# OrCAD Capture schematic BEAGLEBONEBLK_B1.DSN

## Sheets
1 P01_Title Page: title: BeagleBone Black Cover Page; rev: B; note: 450-5500-001
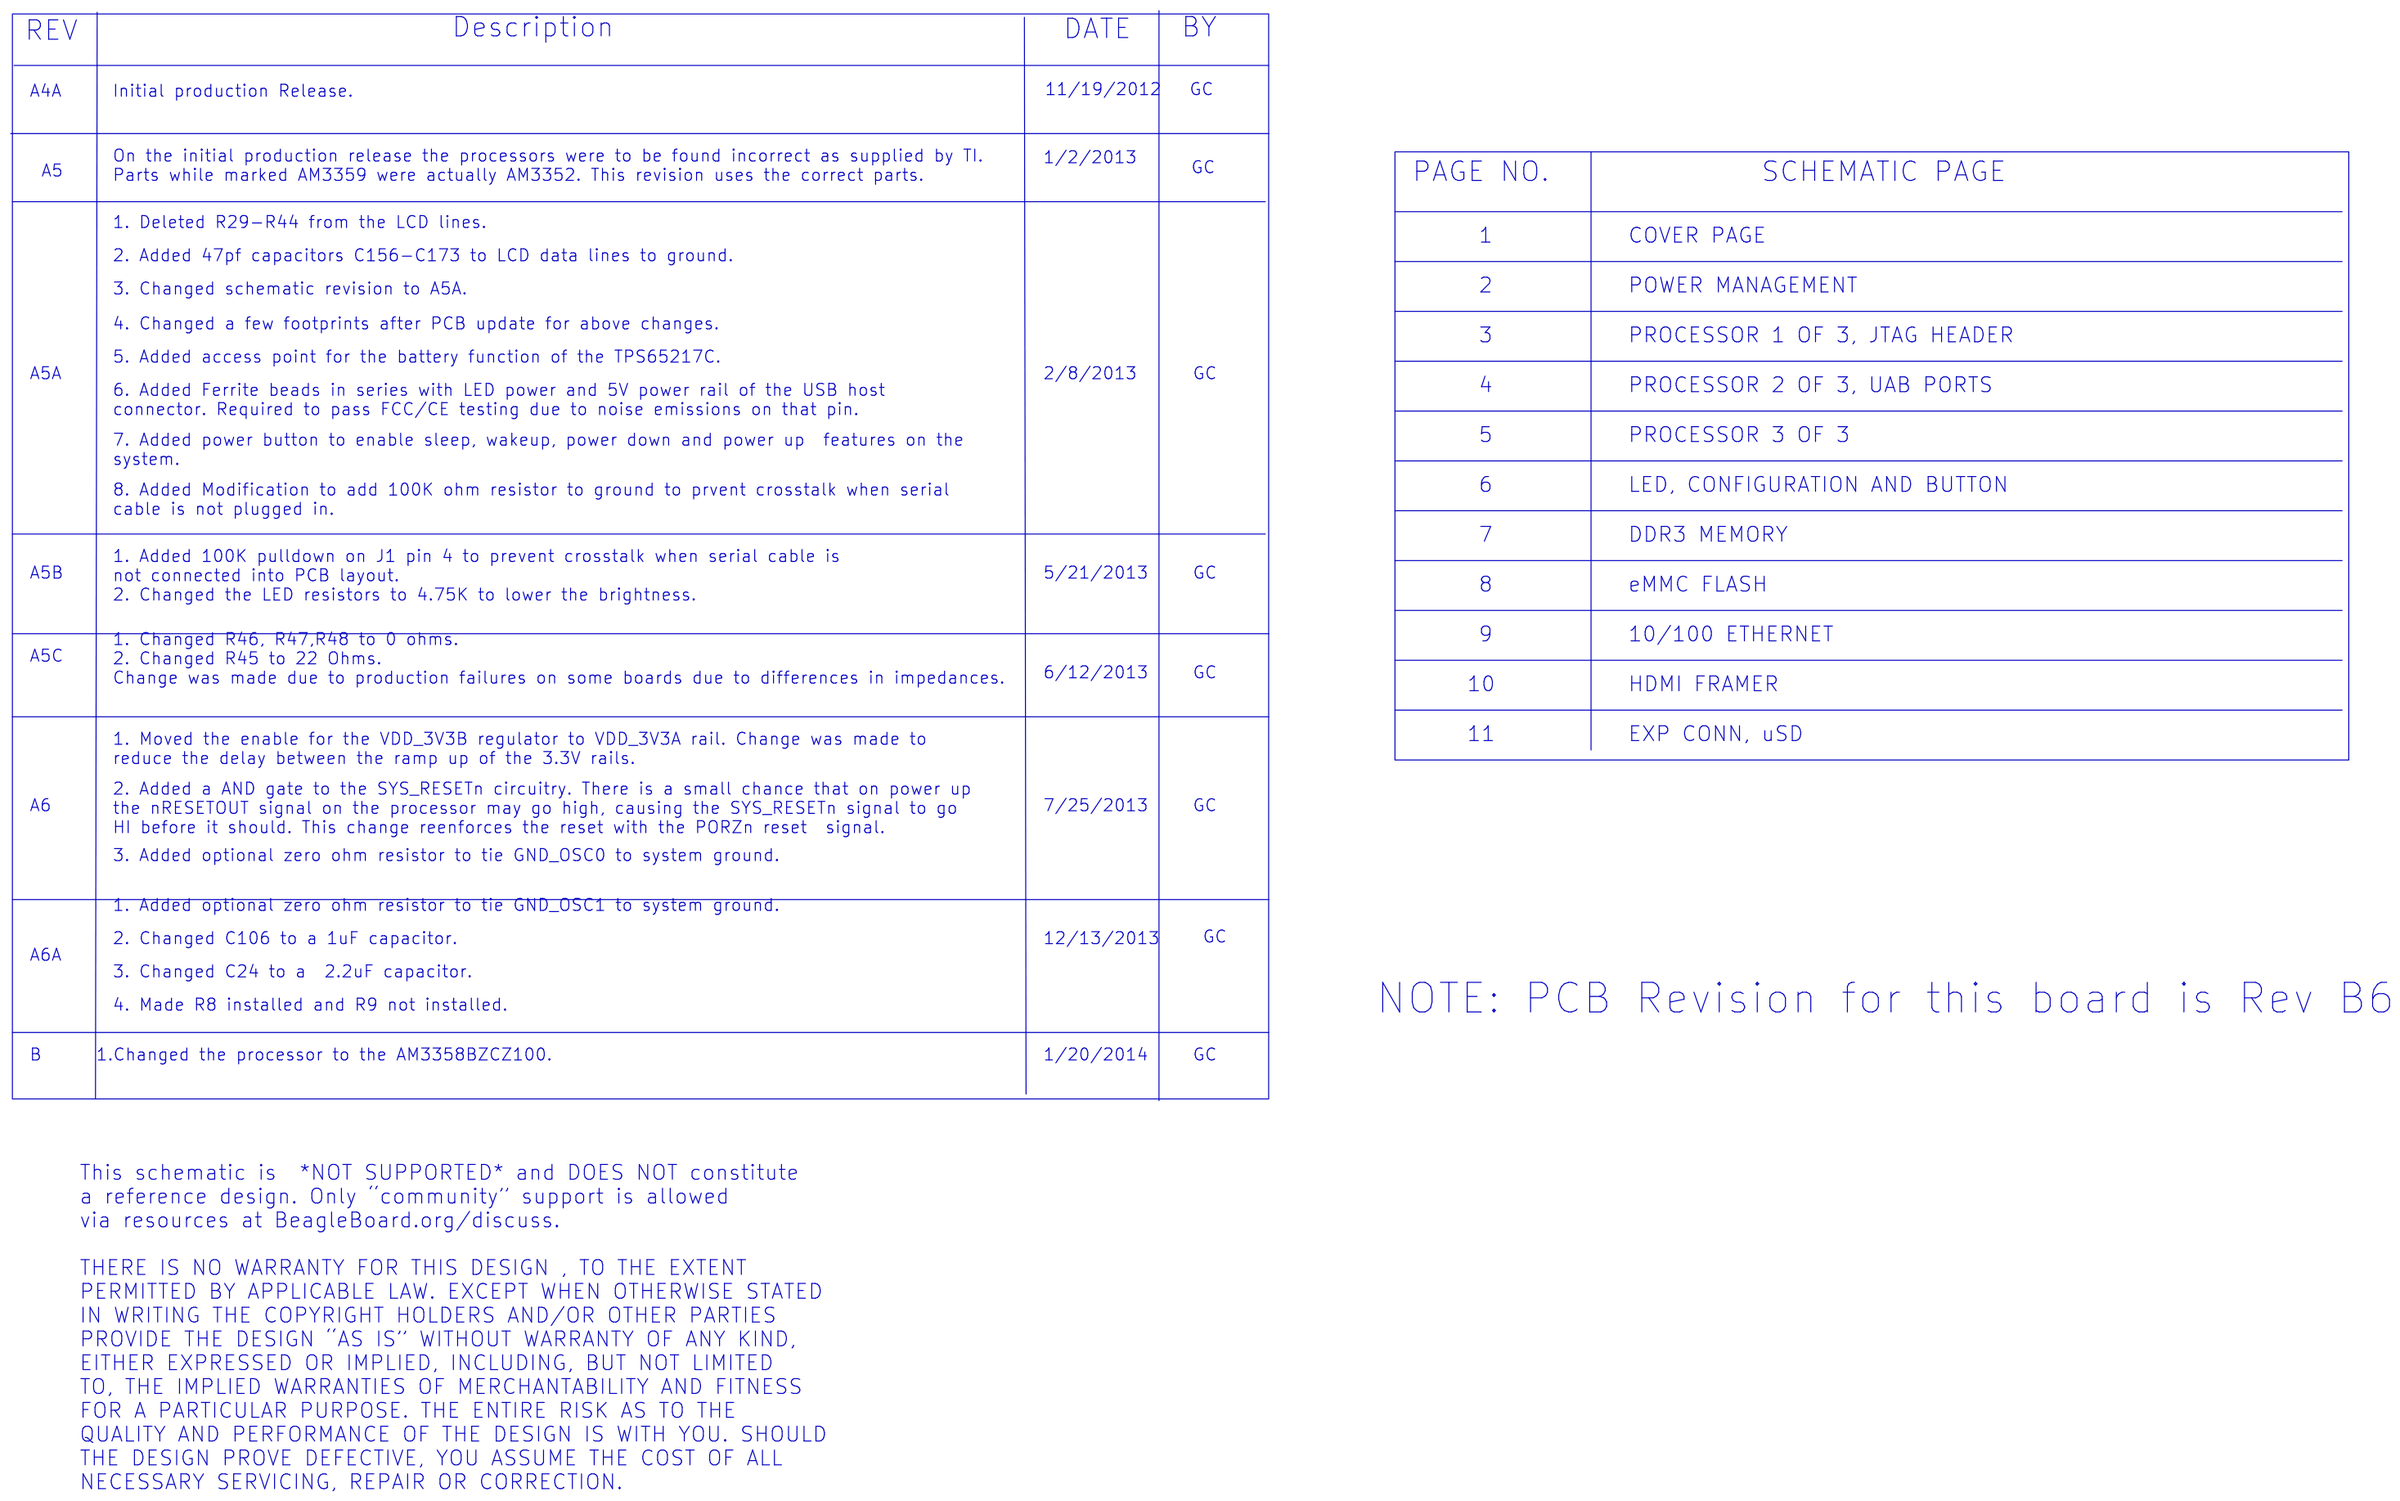
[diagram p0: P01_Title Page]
2 P02_Power Management: size B; title: BeagleBone Black Power Management
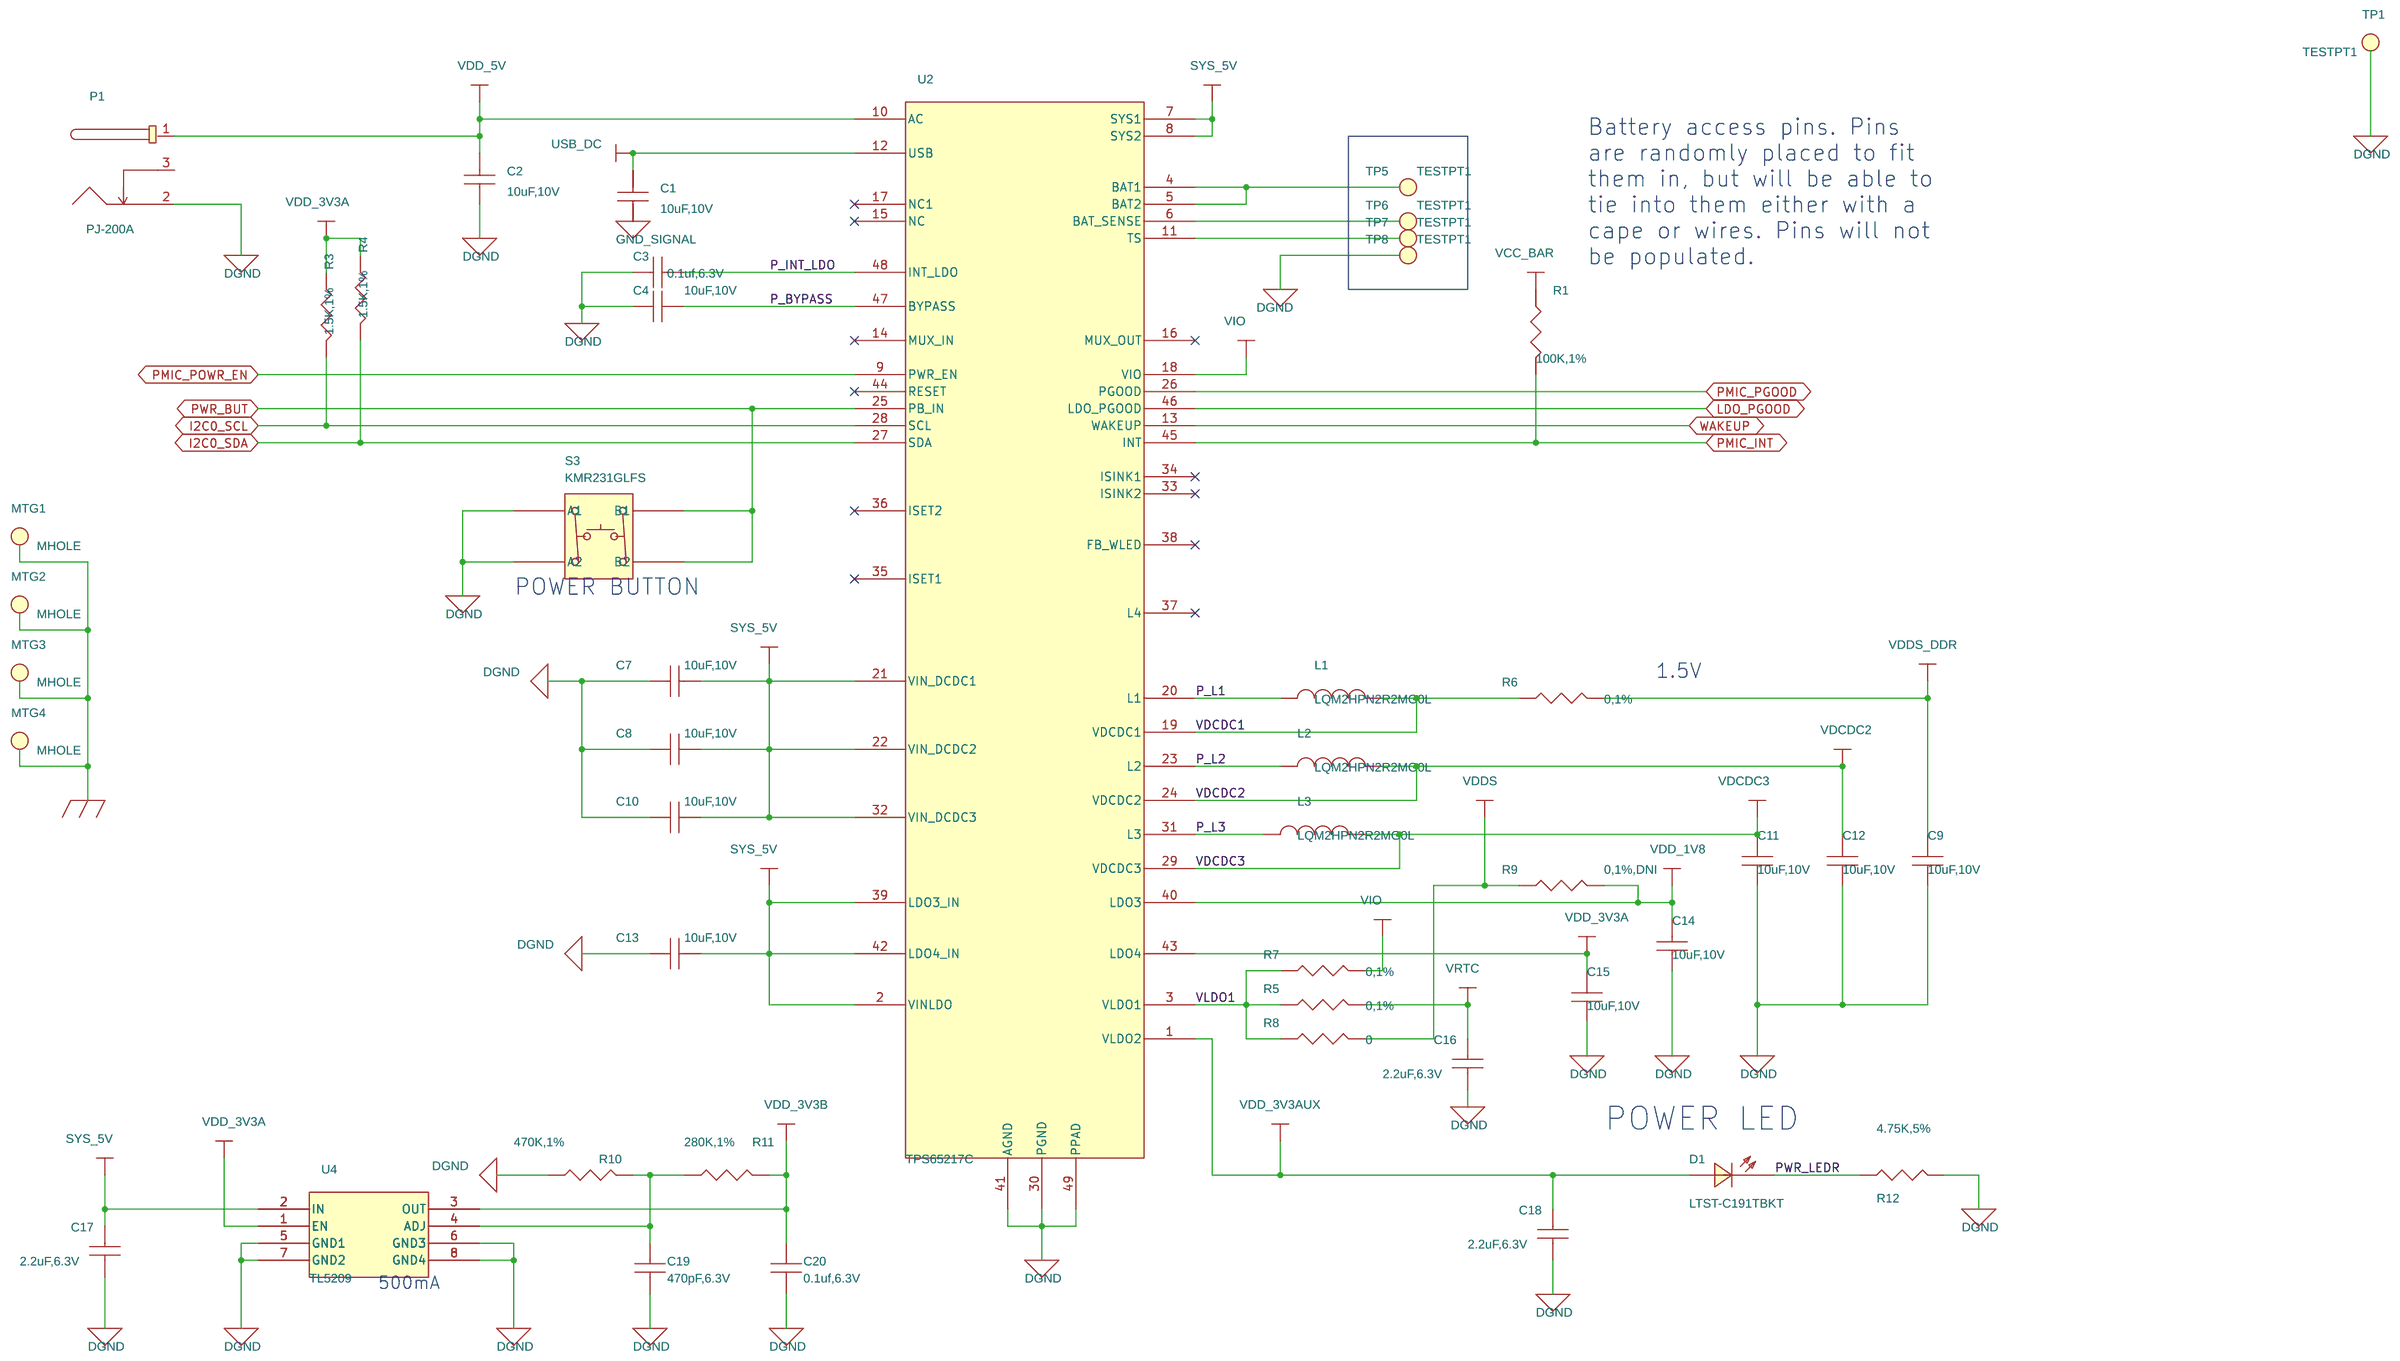
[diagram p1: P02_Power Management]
3 P06_LED, Config: size B; title: BeagleBone Black LED, Configuration, and Reset
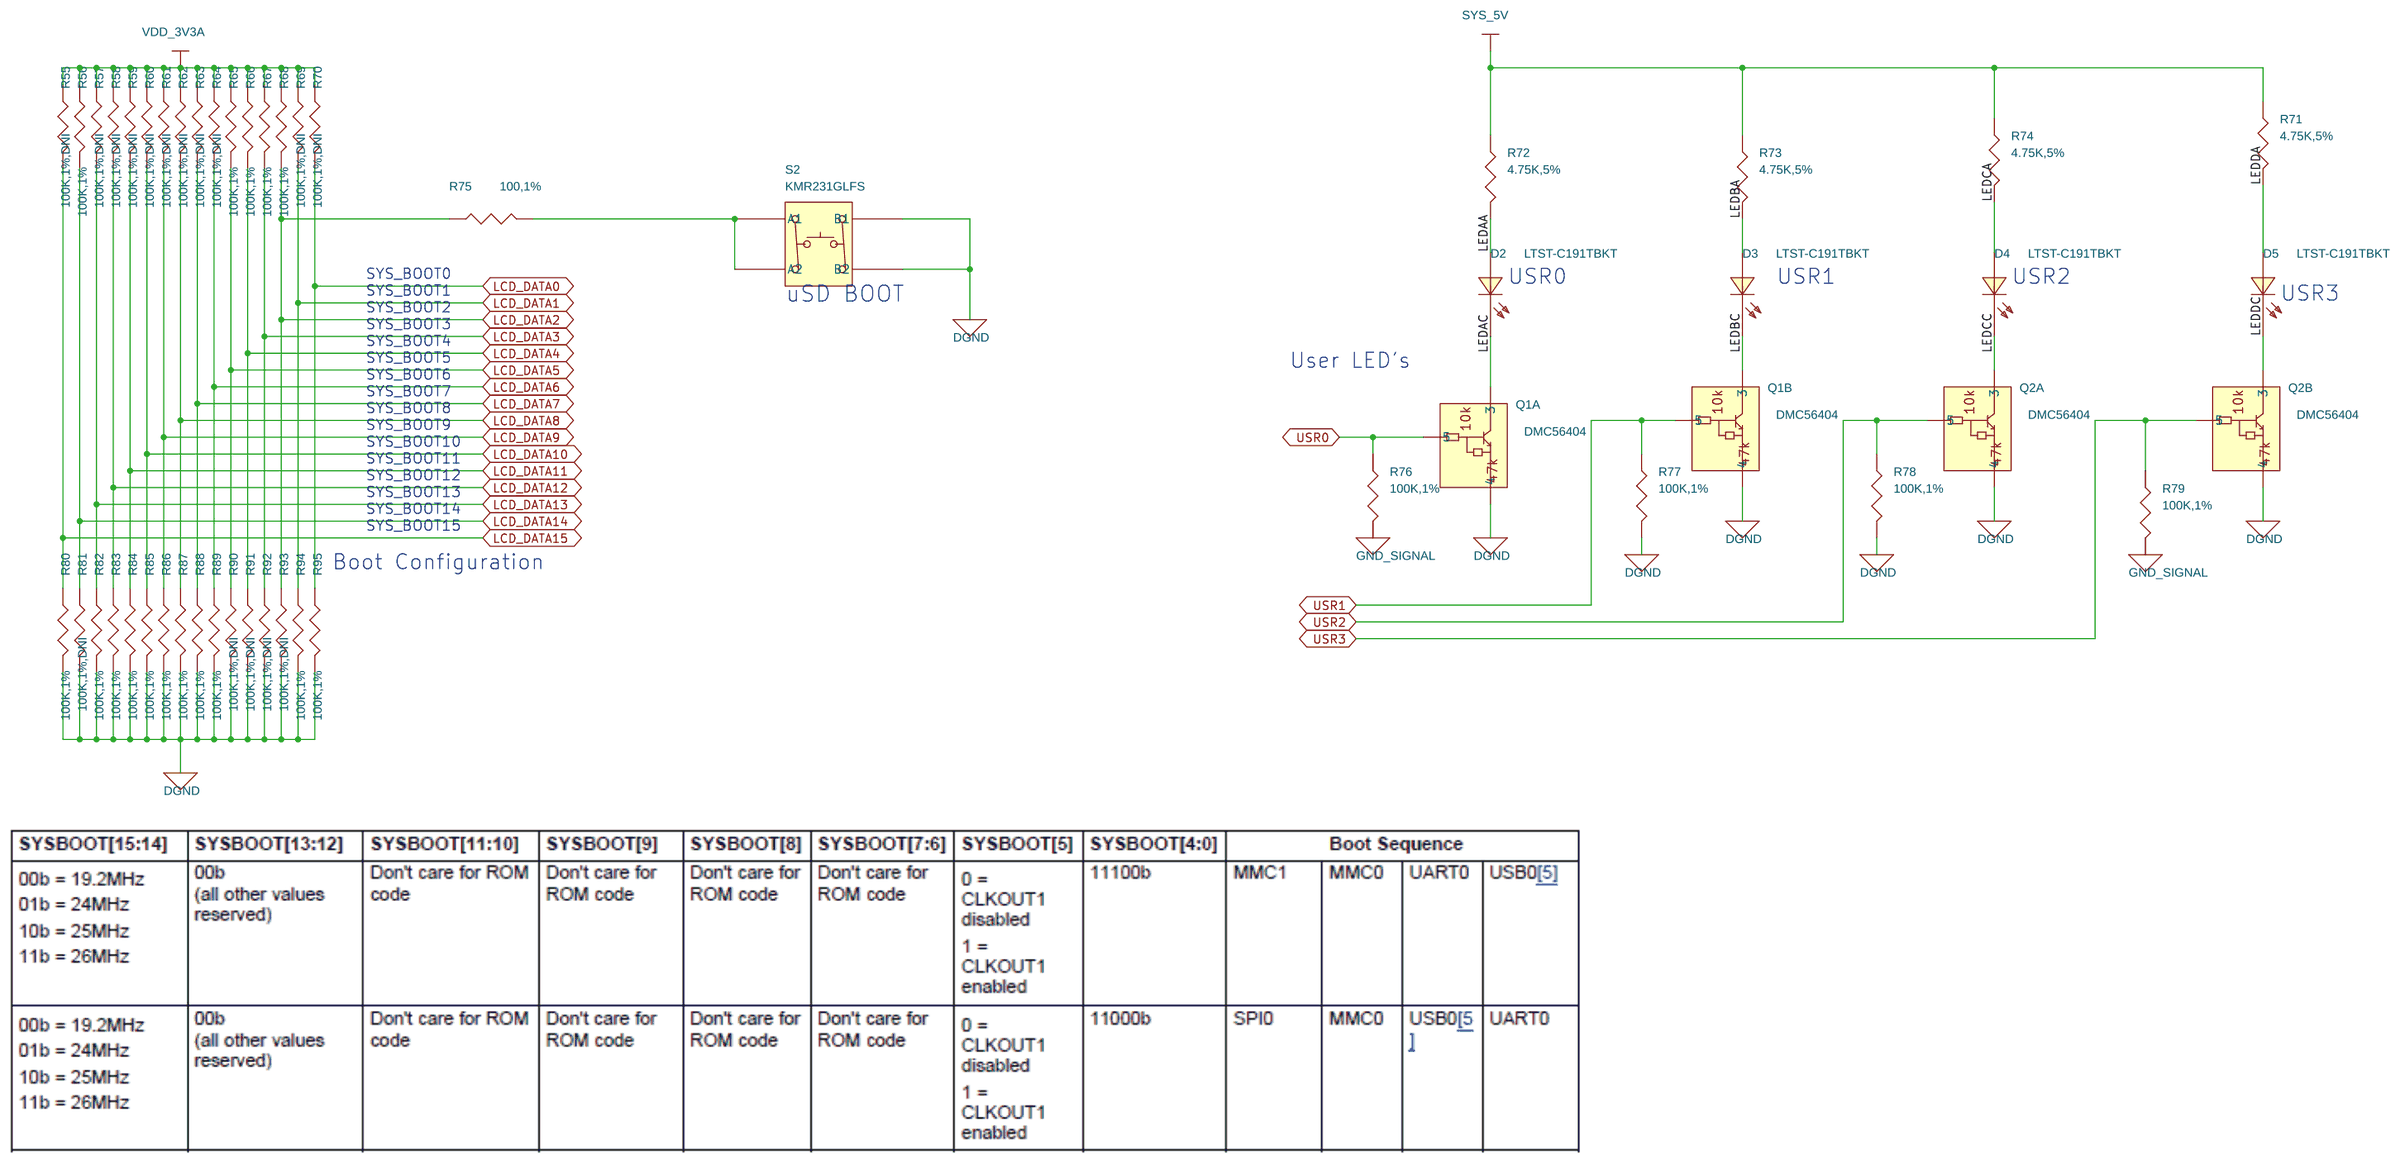
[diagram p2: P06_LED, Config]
4 P07_DDR3 Memory: size B; title: BeagleBone Black DDR3 Memory
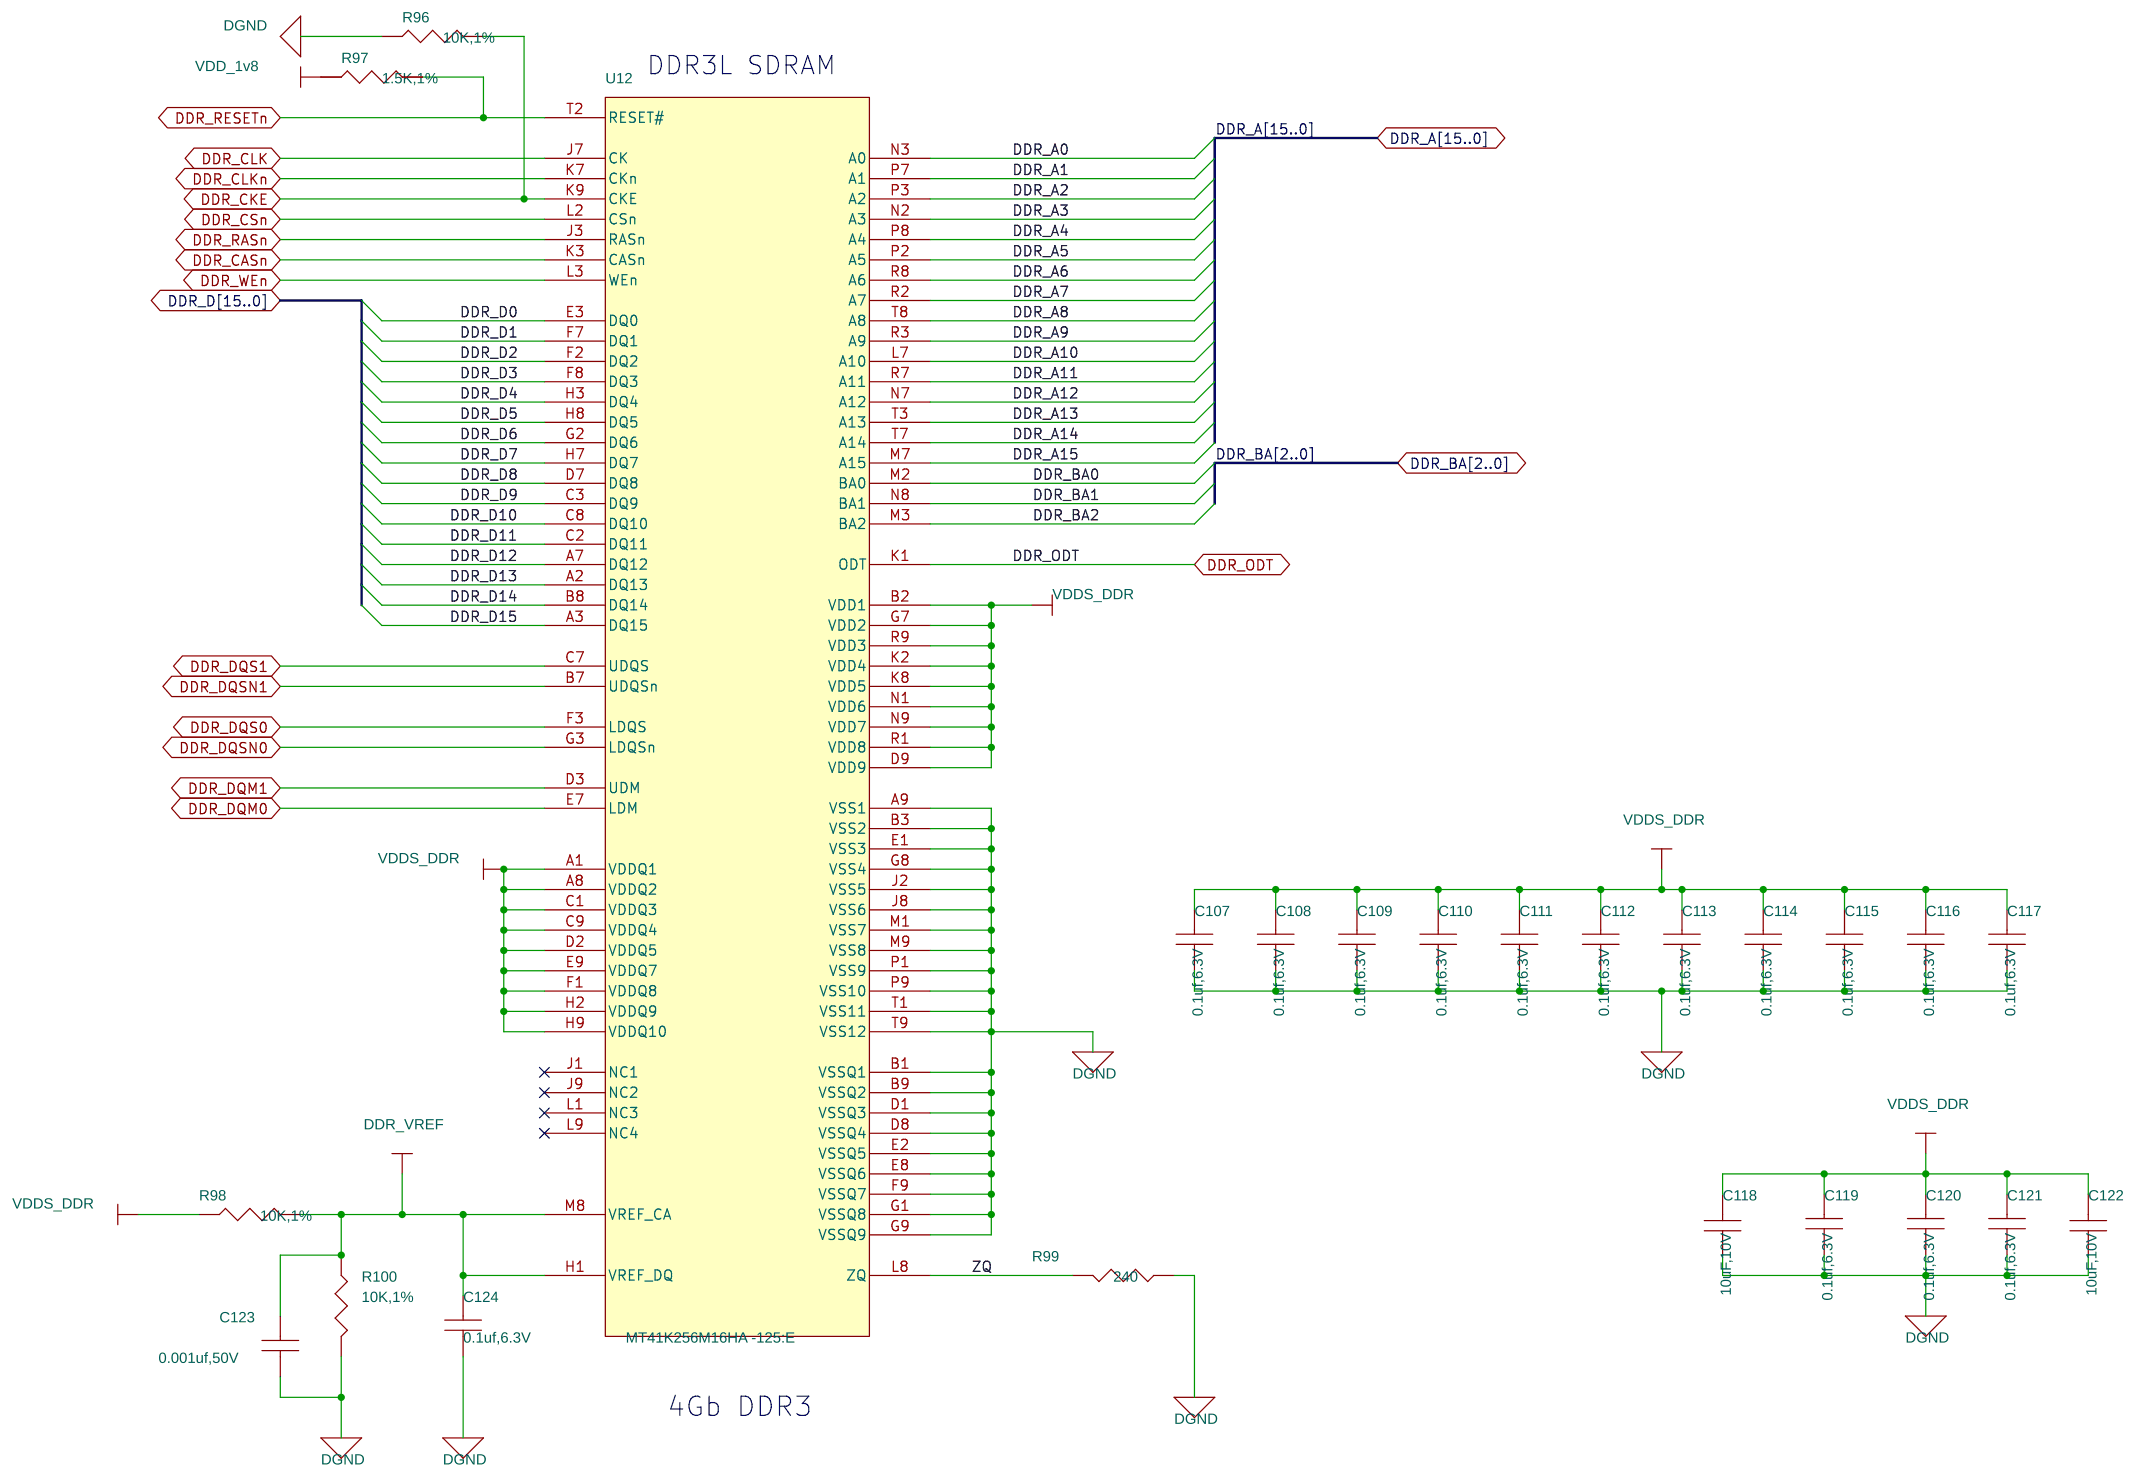
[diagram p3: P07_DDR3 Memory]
5 P08_eMMC FLASH: size B; title: Beagle BoneBlack 2G eMMC
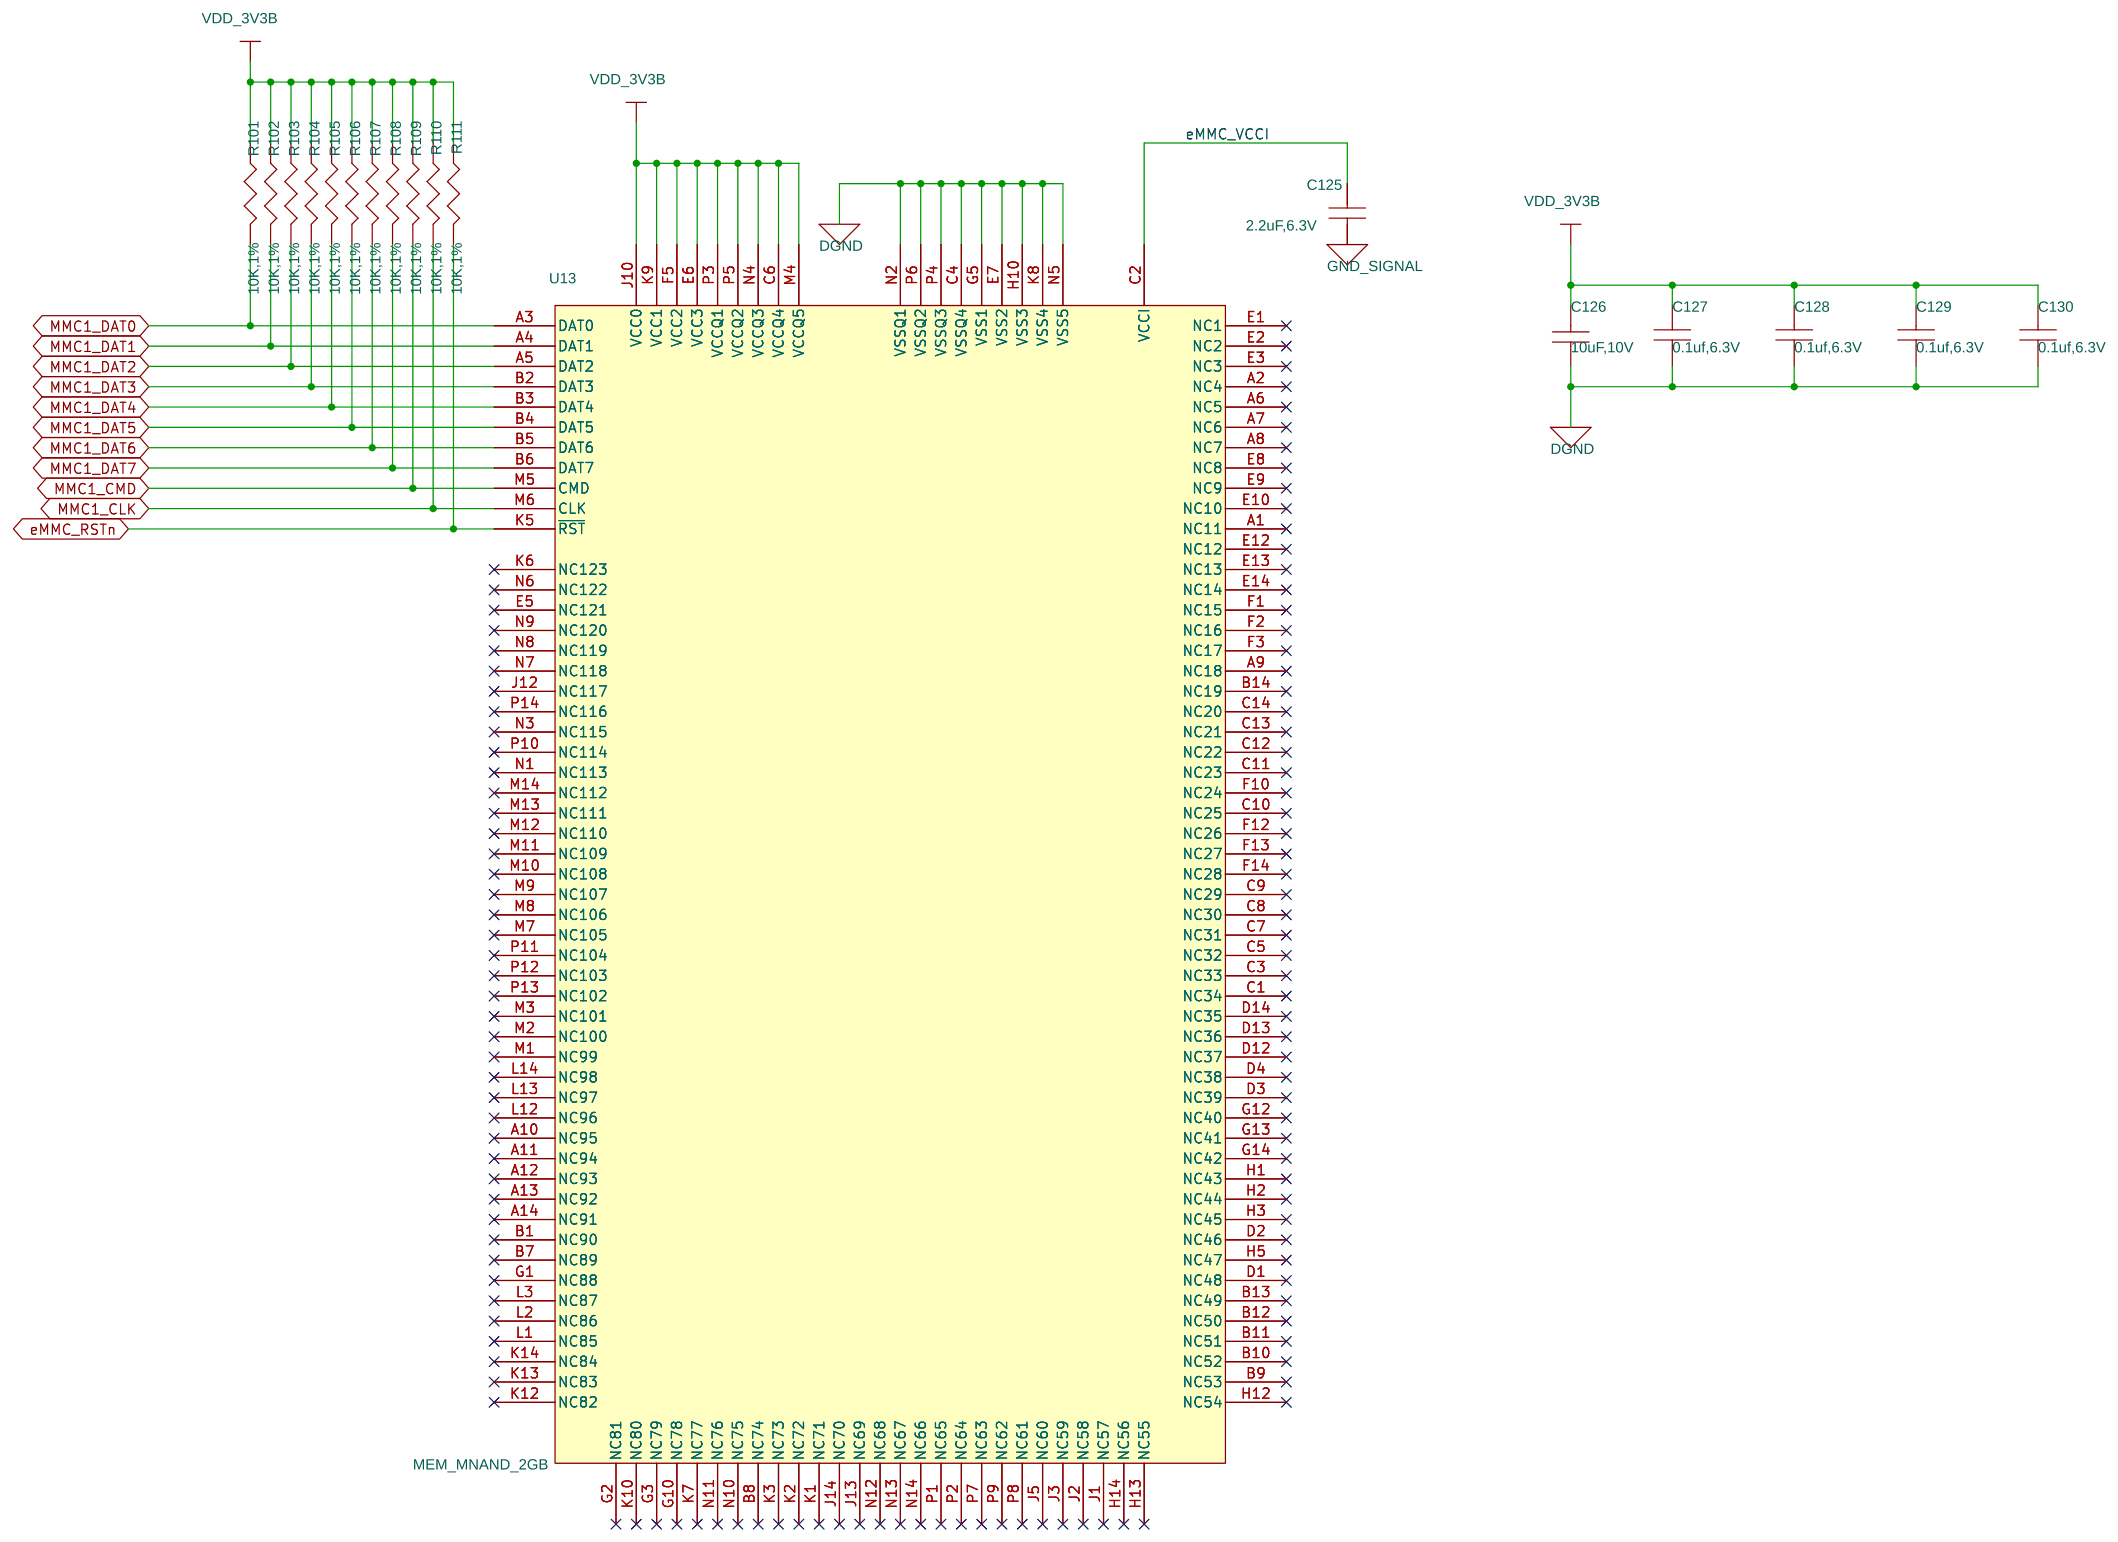
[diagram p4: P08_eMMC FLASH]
6 P10_HDMI: size B; title: BeagleBone Black HDMI Interface
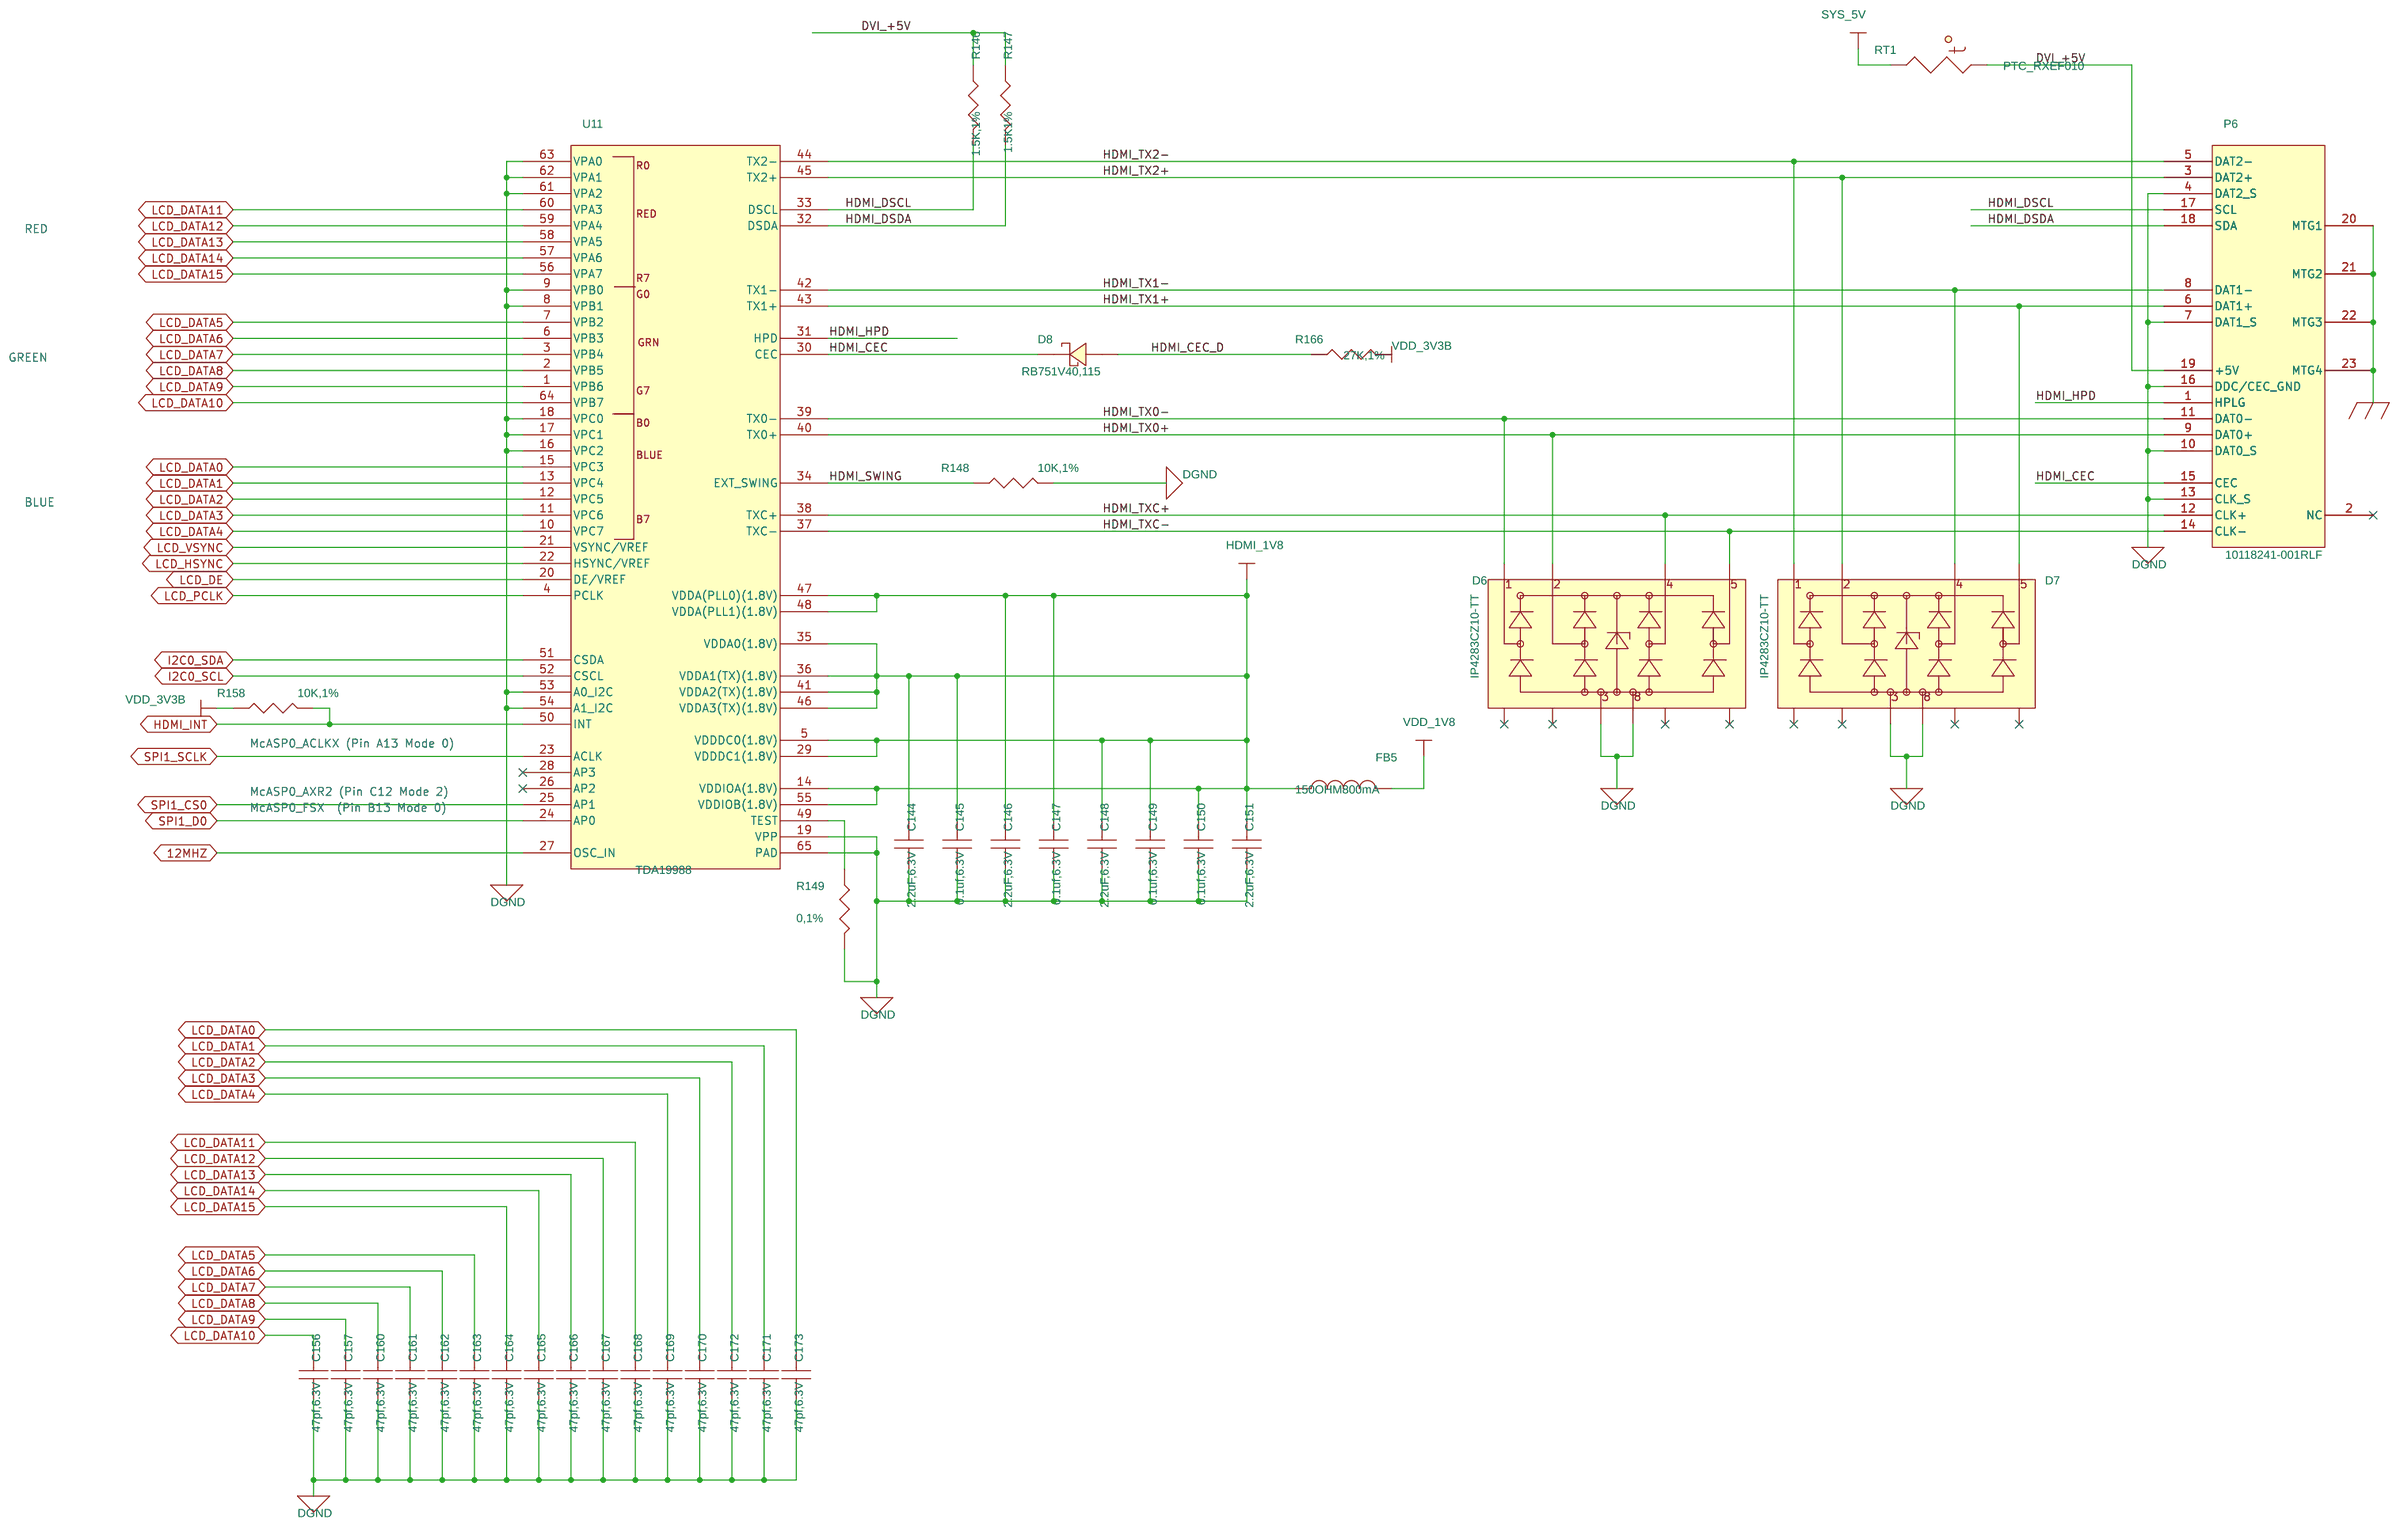
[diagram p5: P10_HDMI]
7 P11_Exp Conn, uSD: size B; title: BeagleBone Black Expansion Headers, uSD.and EEPROM
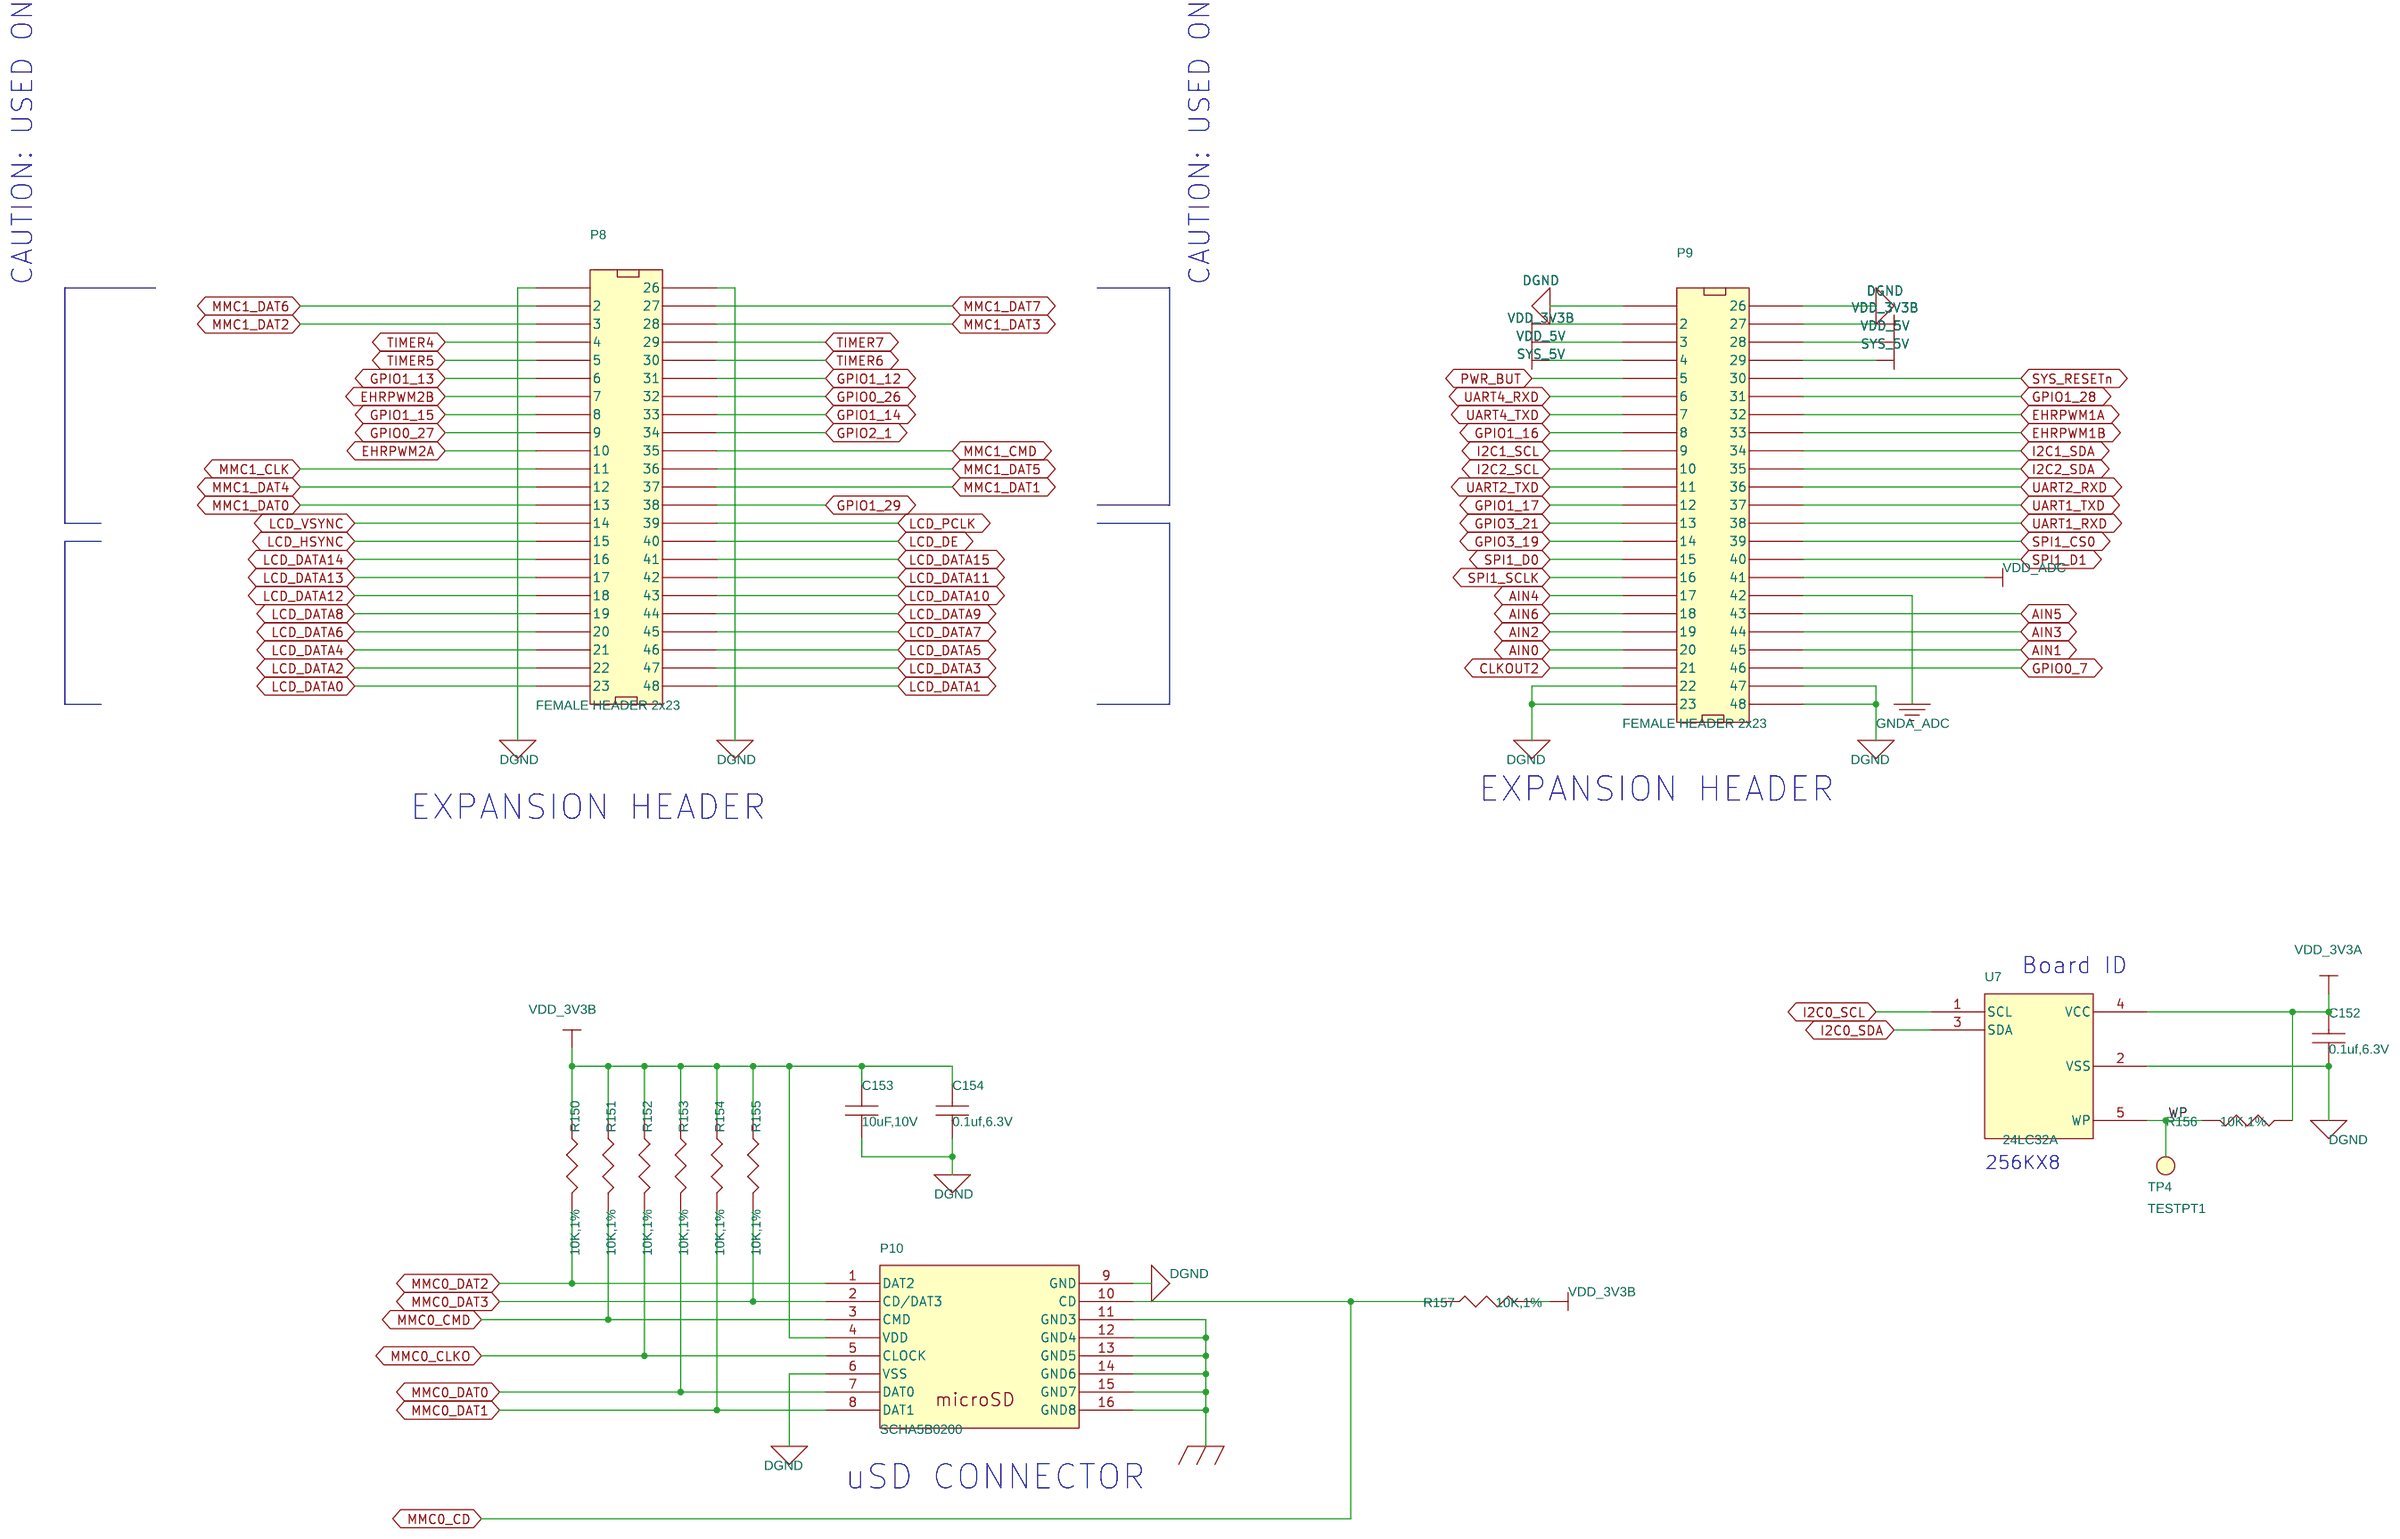
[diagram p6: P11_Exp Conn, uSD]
8 P05_AM335x 3/3: size C; title: BeagleBone Black Processr 3 of 3
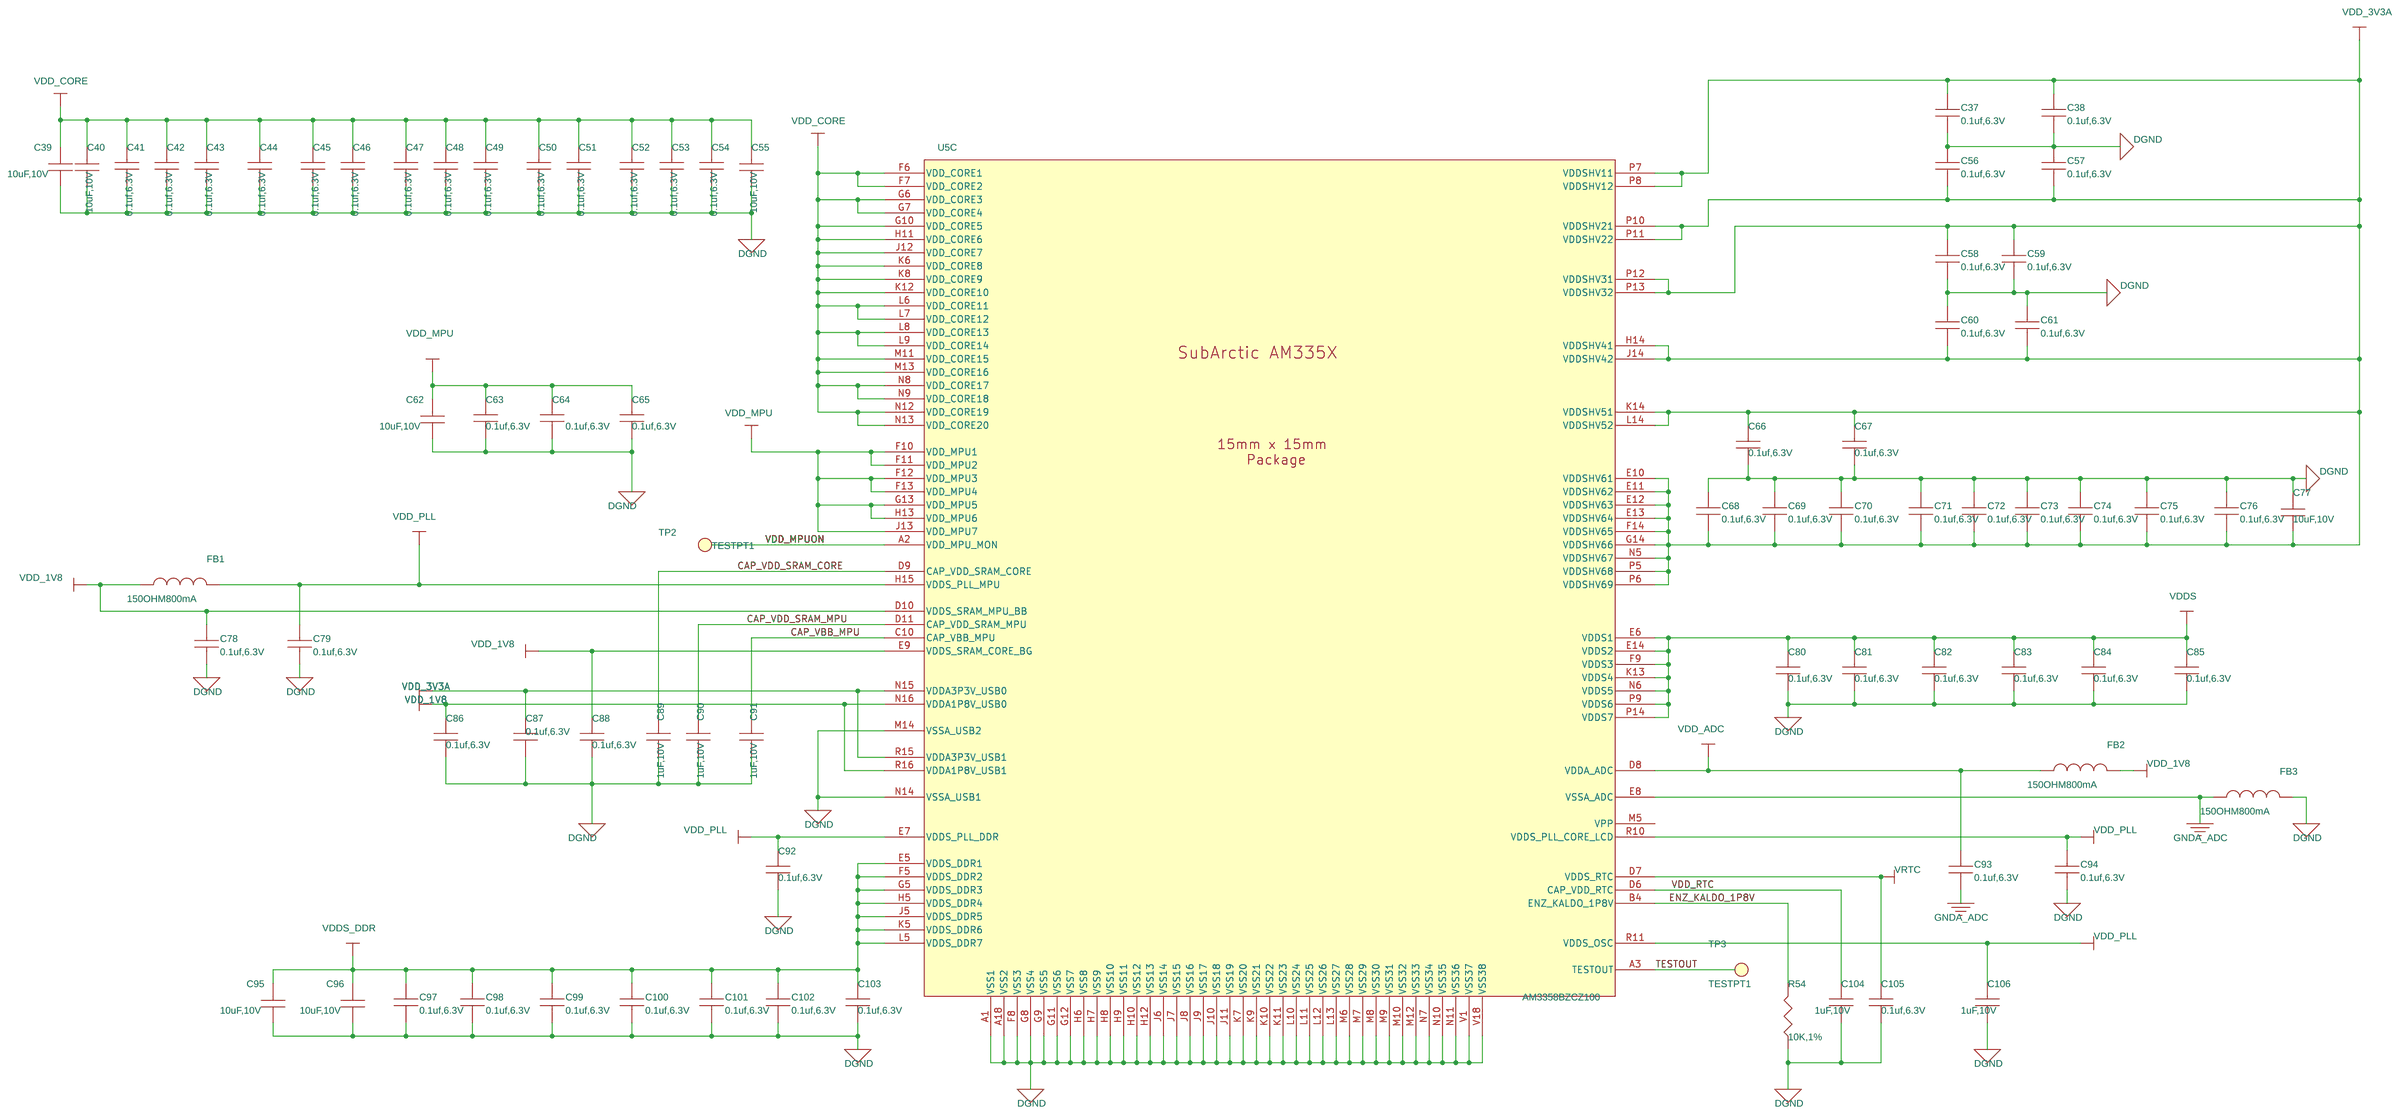
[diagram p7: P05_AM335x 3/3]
9 P03_AM335x 1/3, JTAG: size C; title: BeagleBone Black Processor 1 of 3 and JTAG
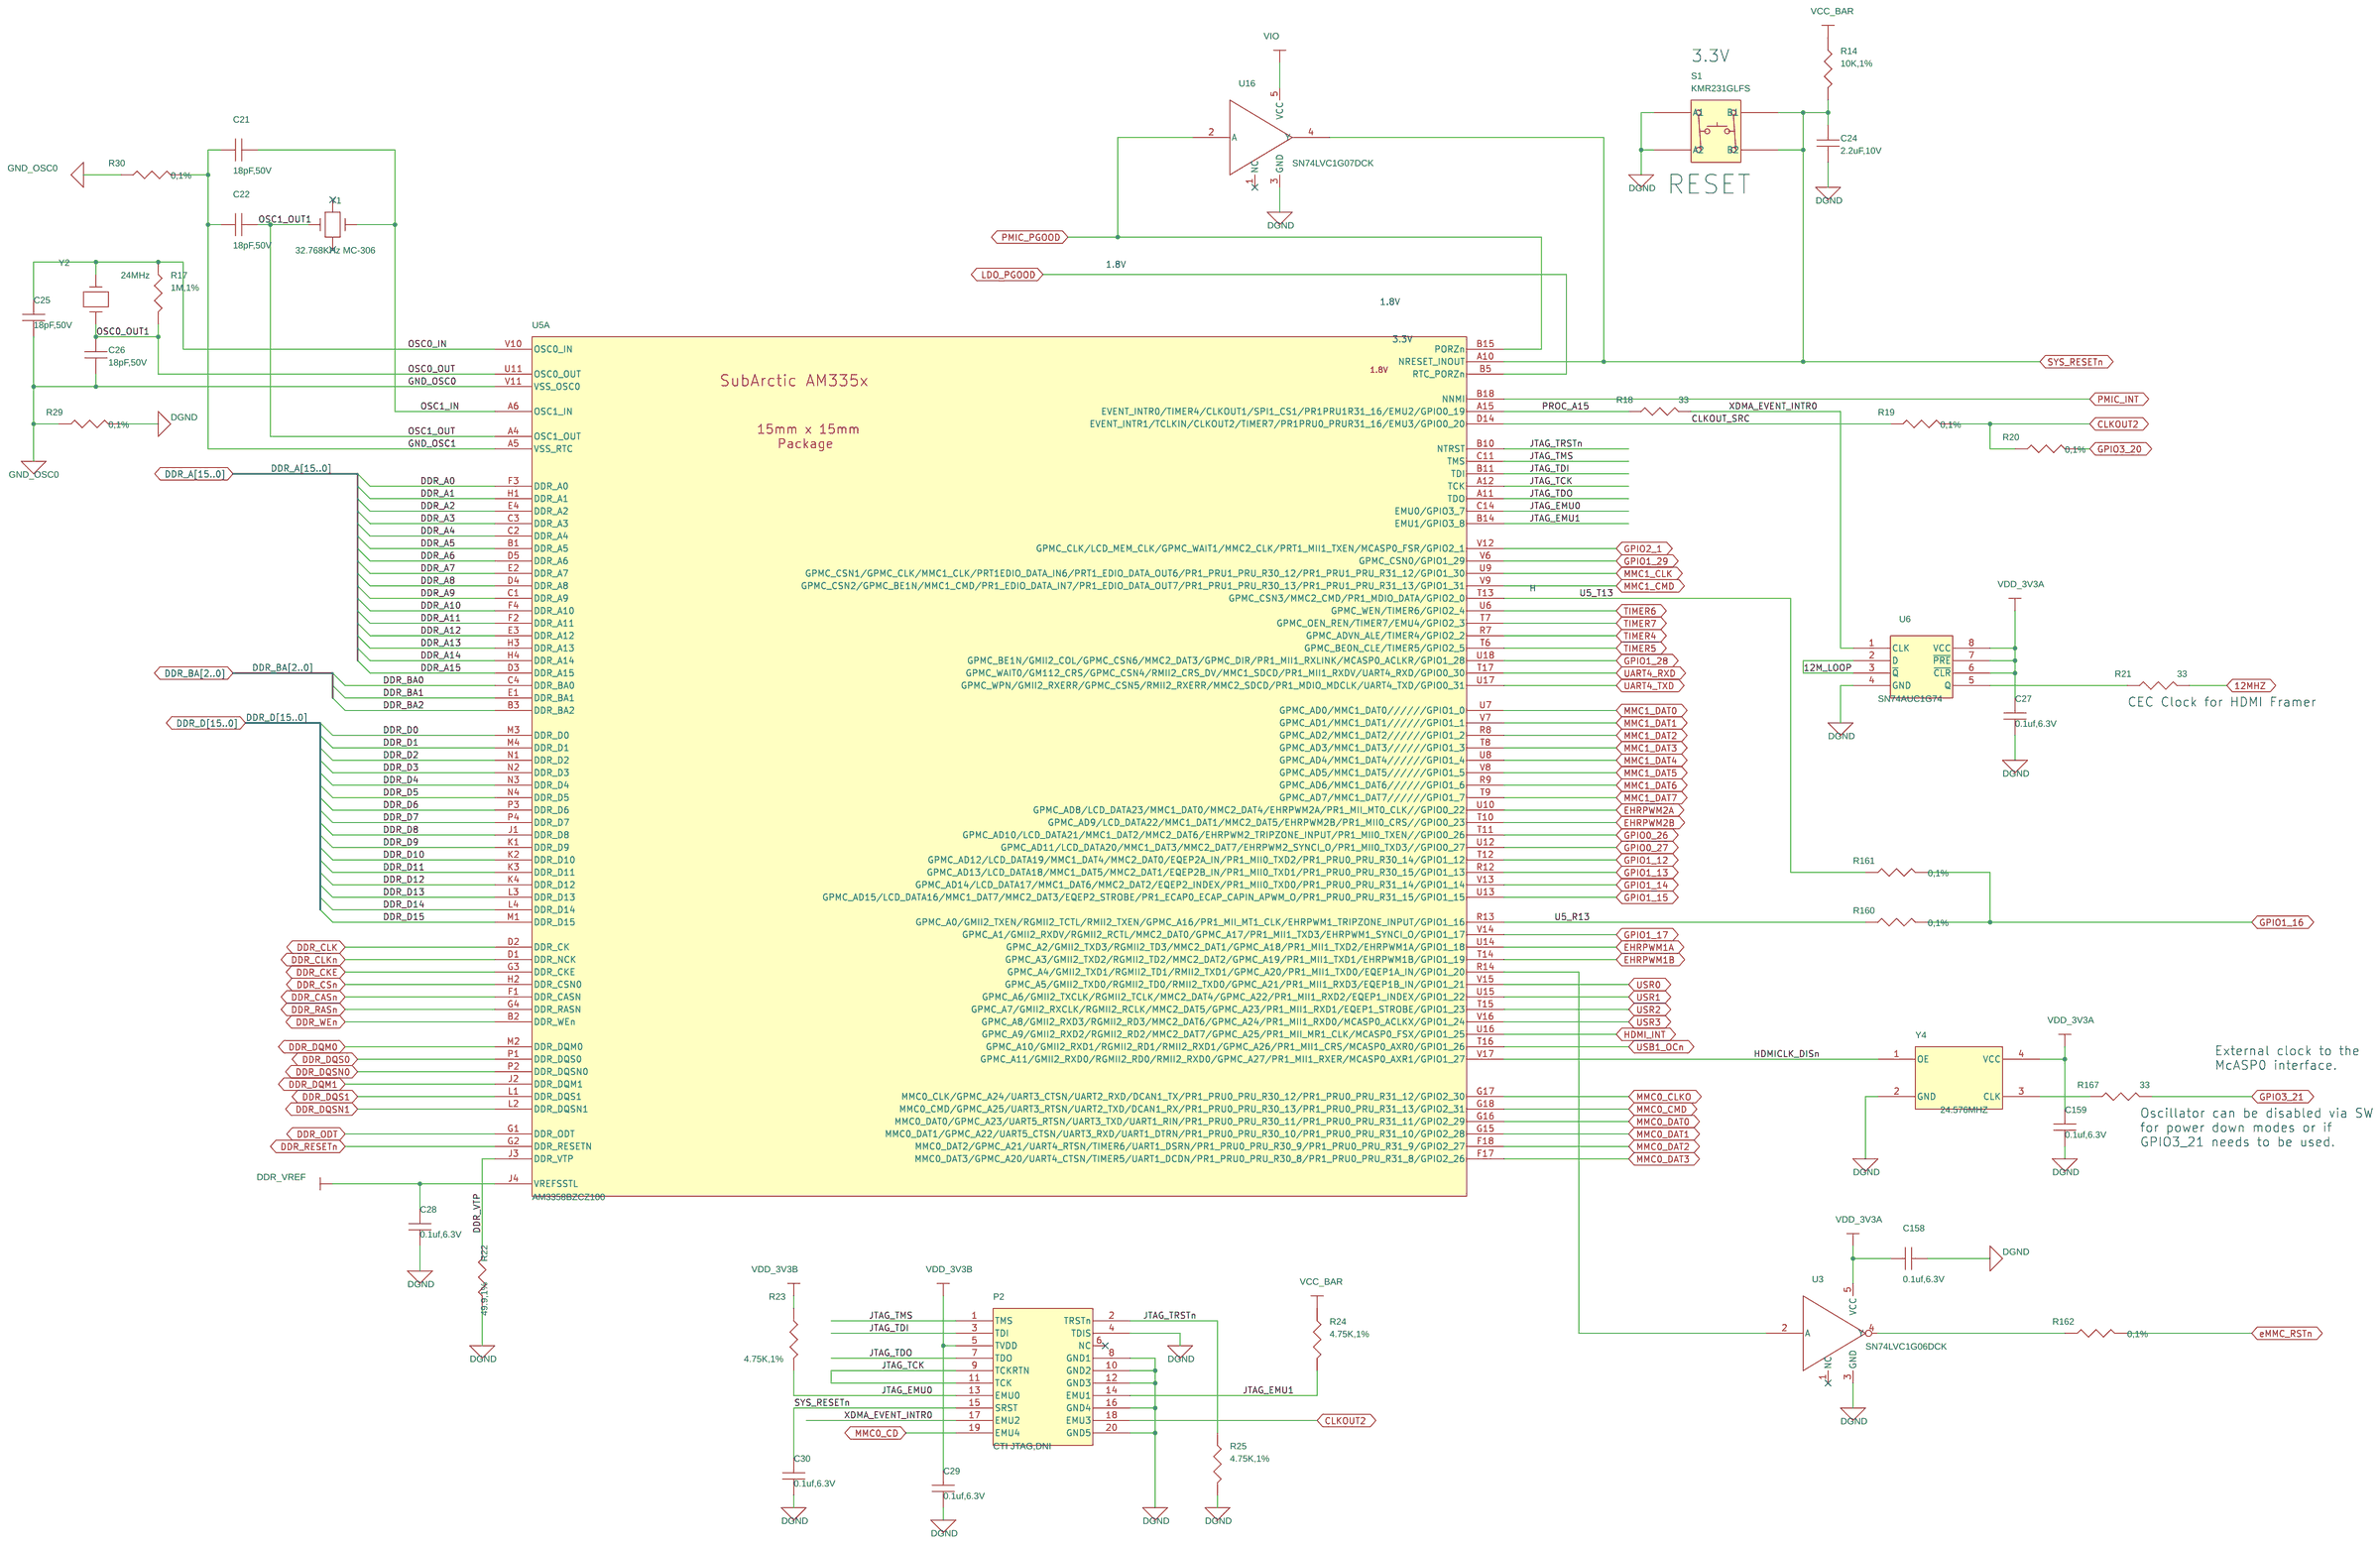
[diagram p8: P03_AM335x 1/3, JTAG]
10 P09_10/100 Ethernet: size B; title: BeagleBone Black Ethernet
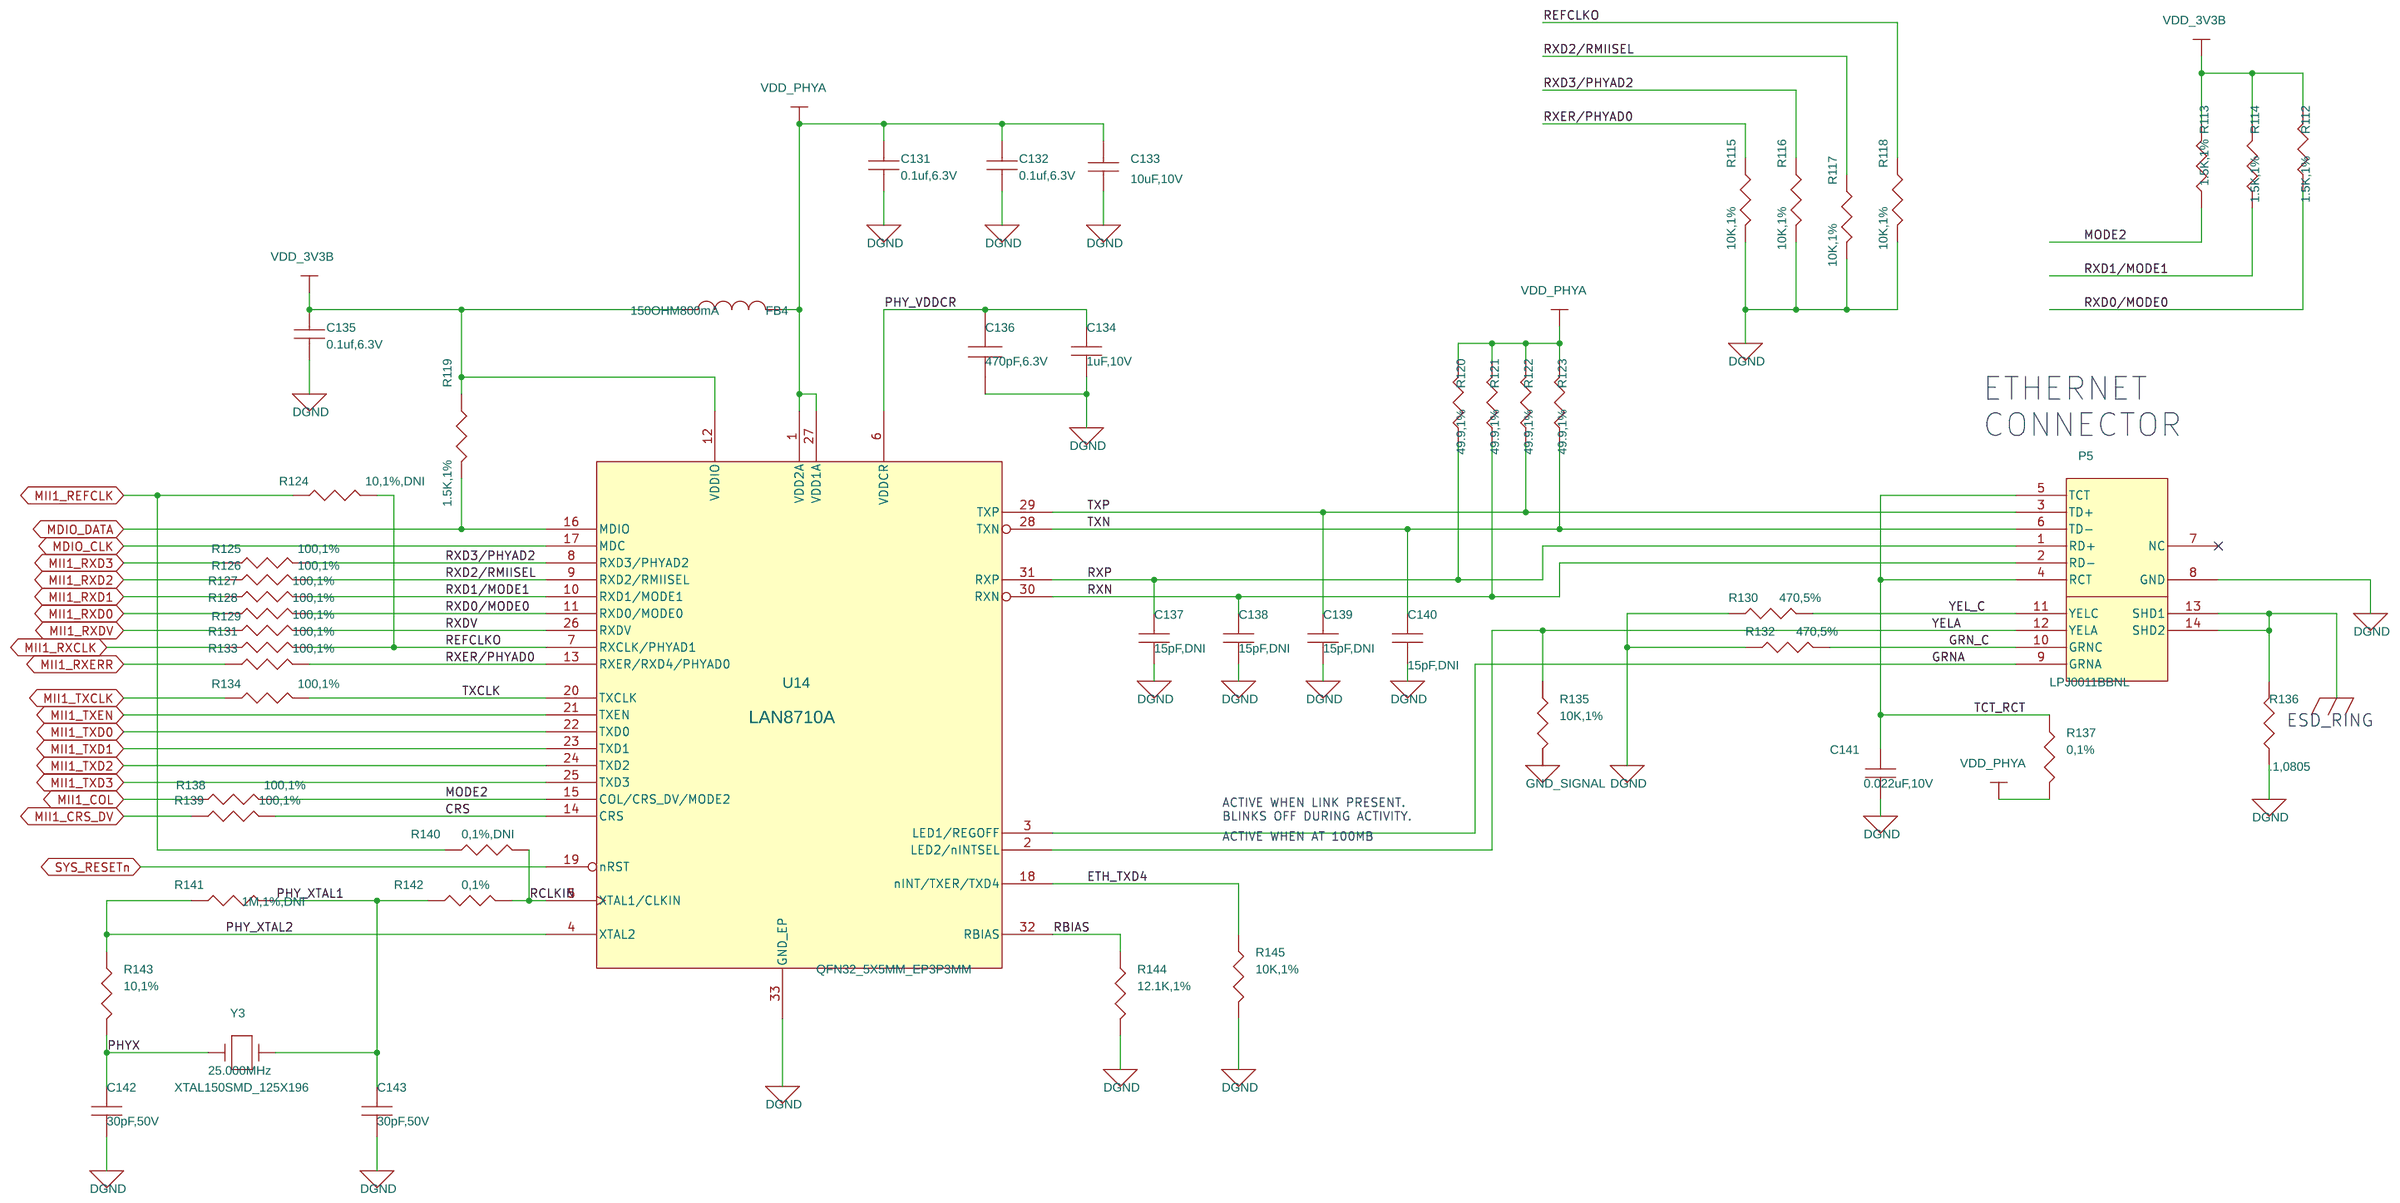
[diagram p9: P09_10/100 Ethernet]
11 P04_AM335x 2/3, USB: size C; title: BeagleBone Black Processor 2 of 3, USB,  and Serial

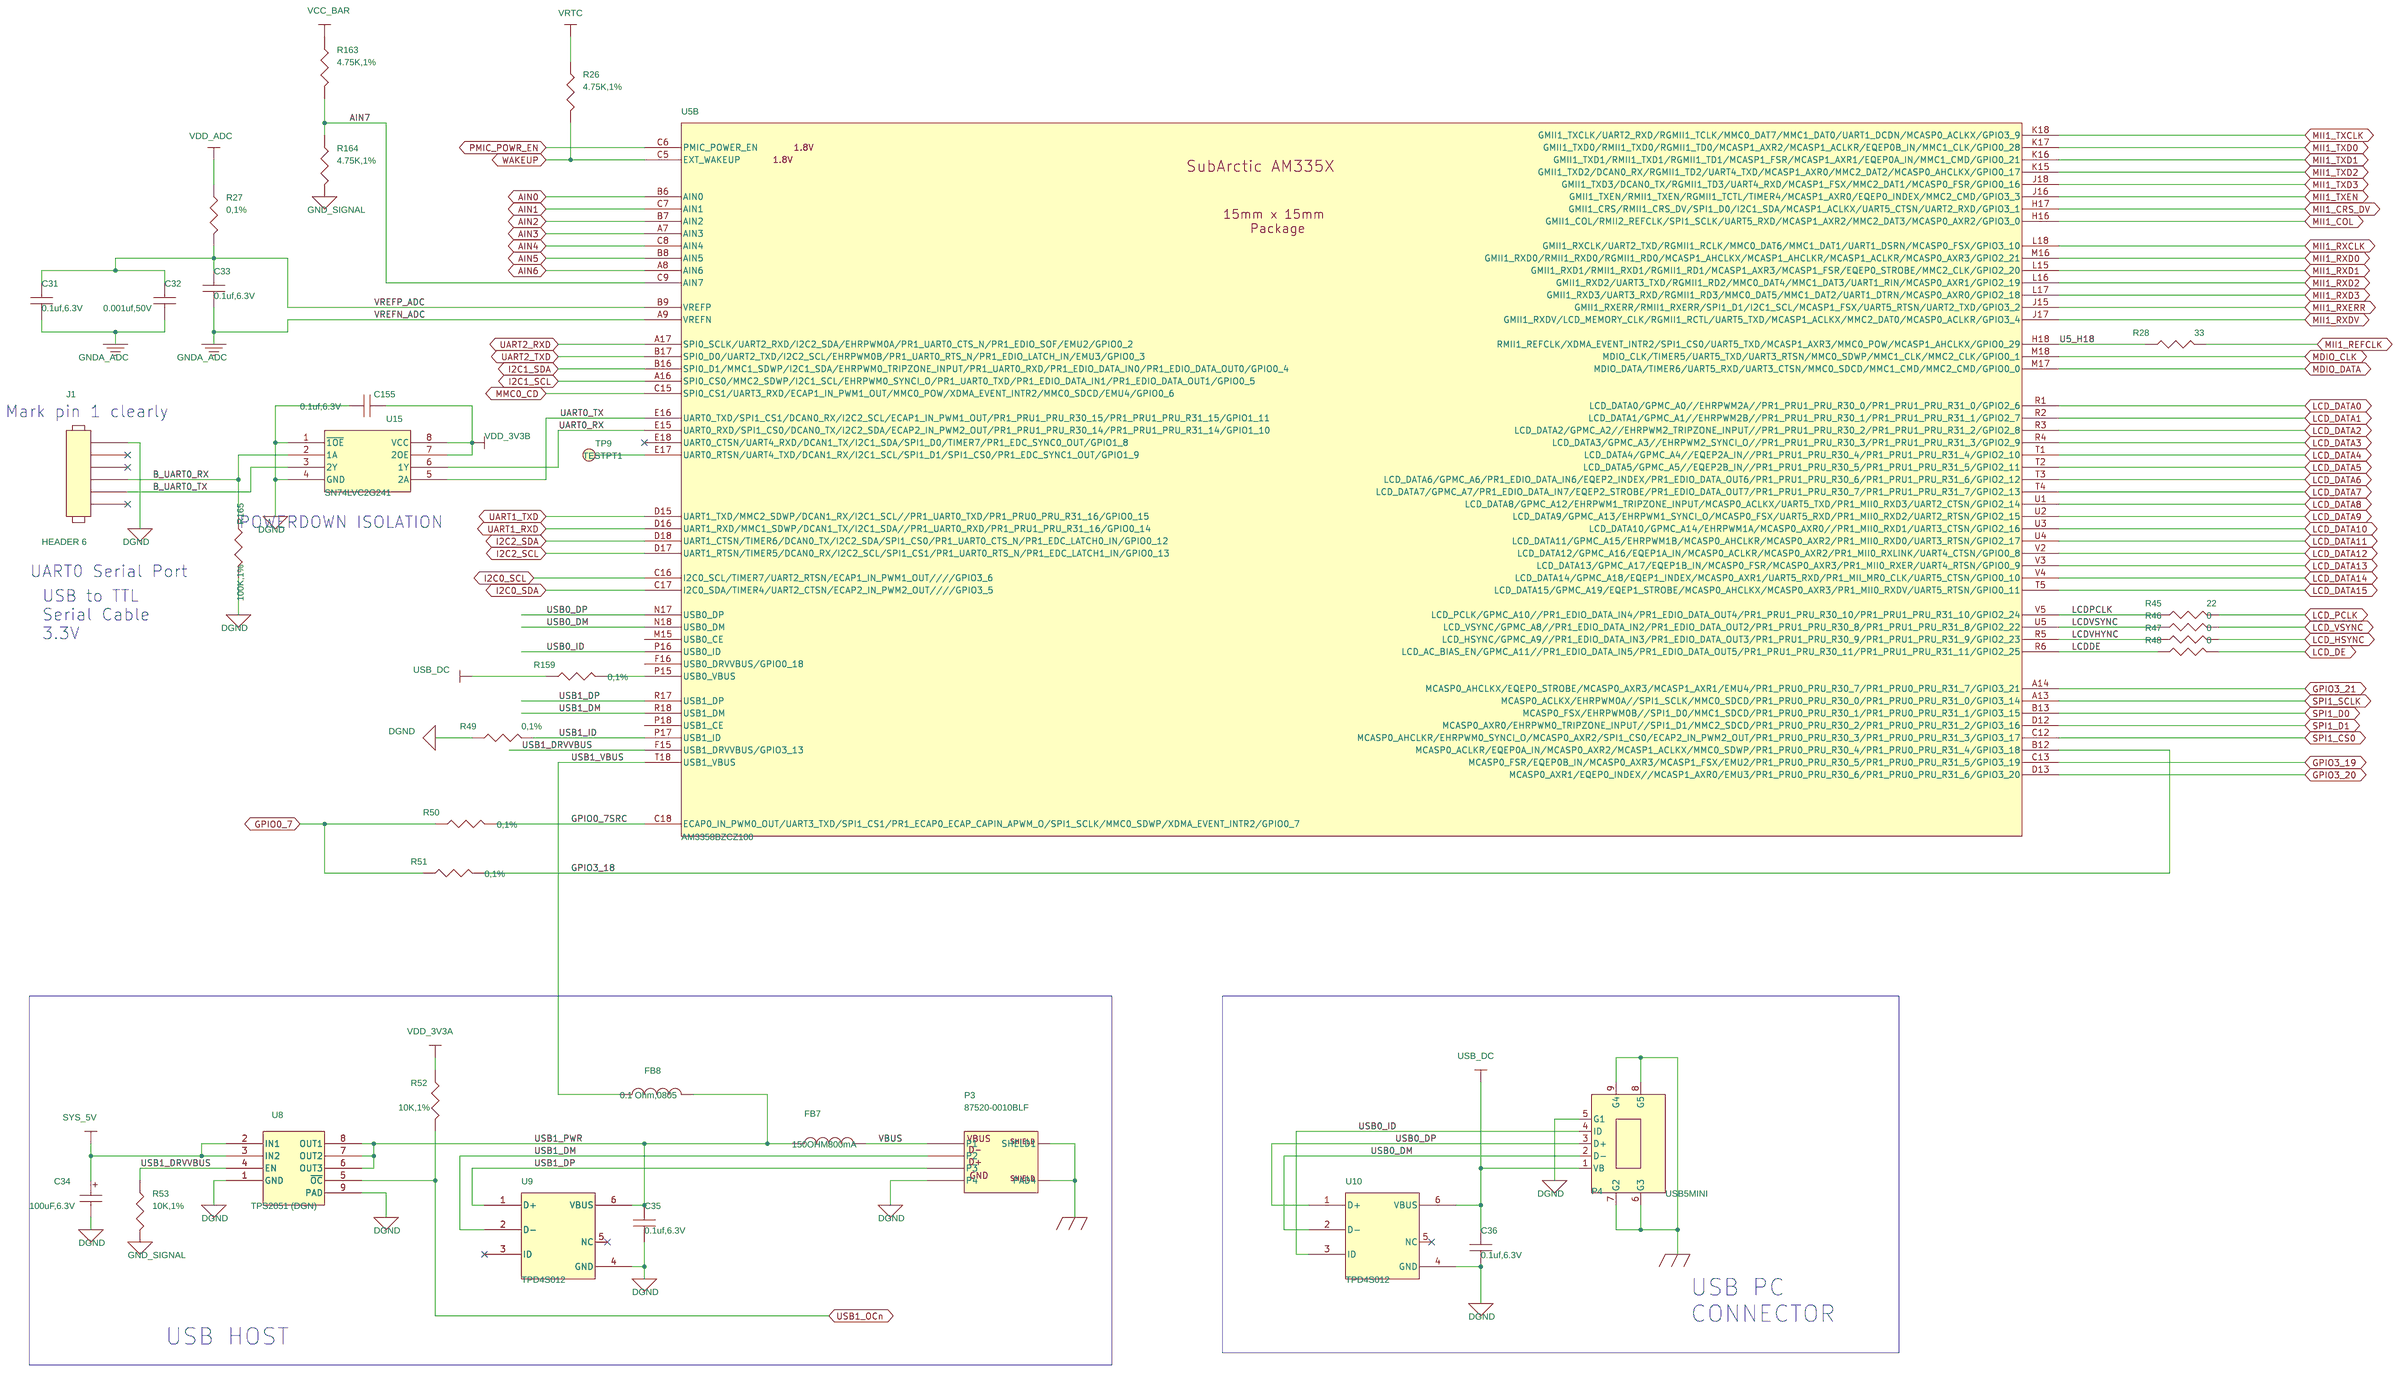
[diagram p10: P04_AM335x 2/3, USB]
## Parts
sheet P02_Power Management
C1  10uF,10V  [805]
C2  10uF,10V  [805]
C3  0.1uf,6.3V  [402]
C4  10uF,10V  [805]
C7  10uF,10V  [805]
C8  10uF,10V  [805]
C9  10uF,10V  [805]
C10  10uF,10V  [805]
C11  10uF,10V  [805]
C12  10uF,10V  [805]
C13  10uF,10V  [805]
C14  10uF,10V  [805]
C15  10uF,10V  [805]
C16  2.2uF,6.3V  [402]
C17  2.2uF,6.3V  [402]
C18  2.2uF,6.3V  [402]
C19  470pF,6.3V  [402]
C20  0.1uf,6.3V  [402]
D1  LTST-C191TBKT  [LED_0603]
L1  LQM2HPN2R2MG0L  [2520]
L2  LQM2HPN2R2MG0L  [2520]
L3  LQM2HPN2R2MG0L  [2520]
MTG1  MHOLE  [MTGH200C125D_PL]
MTG2  MHOLE  [MTGH200C125D_PL]
MTG3  MHOLE  [MTGH200C125D_PL]
MTG4  MHOLE  [MTGH200C125D_PL]
P1  PJ-200A  [CONN3-PWR-PJ102A]
R1  100K,1%  [402]
R3  1.5K,1%  [402]
R4  1.5K,1%  [402]
R5  0,1%  [402]
R6  0,1%  [402]
R7  0,1%  [402]
R8  0  [402]
R9  0,1%,DNI  [402]
R10  470K,1%  [402]
R11  280K,1%  [402]
R12  4.75K,5%  [402]
S3  KMR231GLFS  [SW4SMD_63X161LS]
TP1  TESTPT1  [tp1-8040]
TP5  TESTPT1  [TP60C33D]
TP6  TESTPT1  [TP60C33D]
TP7  TESTPT1  [TP60C33D]
TP8  TESTPT1  [TP60C33D]
U2  TPS65217C  [U_48_RSL]
U4  TL5209  [SO8-25X75]
sheet P03_AM335x 1/3, JTAG
C21  18pF,50V  [402]
C22  18pF,50V  [402]
C24  2.2uF,10V  [402]
C25  18pF,50V  [402]
C26  18pF,50V  [402]
C27  0.1uf,6.3V  [402]
C28  0.1uf,6.3V  [402]
C29  0.1uf,6.3V  [402]
C30  0.1uf,6.3V  [402]
C158  0.1uf,6.3V  [402]
C159  0.1uf,6.3V  [402]
P2  CTI JTAG,DNI  [HEADER10X2_SMD]
R14  10K,1%  [402]
R17  1M,1%  [402]
R18  33  [0402]
R19  0,1%  [402]
R20  0,1%  [402]
R21  33  [0402]
R22  49.9,1%  [402]
R23  4.75K,1%  [402]
R24  4.75K,1%  [402]
R25  4.75K,1%  [402]
R29  0,1%  [402]
R30  0,1%  [402]
R160  0,1%  [402]
R161  0,1%  [402]
R162  0,1%  [402]
R167  33  [0402]
S1  KMR231GLFS  [SW4SMD_63X161LS]
U3  SN74LVC1G06DCK  [DCK5_2P15X1P4]
U6  SN74AUC1G74  [SOP8_DCT]
U16  SN74LVC1G07DCK  [DCK5_2P15X1P4]
Y1  32.768KHz MC-306  [XTAL4_126-216SMD]
Y2  24MHz  [XTAL150SMD_125X196]
Y4  24.576MHZ  [OSC4_61X65LS_79X98SMD]
sheet P04_AM335x 2/3, USB
C31  0.1uf,6.3V  [402]
C32  0.001uf,50V  [402]
C33  0.1uf,6.3V  [402]
C34  100uF,6.3V  [RD205SMD_250D]
C35  0.1uf,6.3V  [402]
C36  0.1uf,6.3V  [402]
C155  0.1uf,6.3V  [402]
FB7  150OHM800mA  [sm-7351-ind-0805]
FB8  0.1 Ohm,0805  [sm-7351-ind-0805]
J1  HEADER 6  [SIP6]
P3  87520-0010BLF  [USB_A_SH]
P4  USB5MINI  [USB5MINI_4SHIELDED_SMD-5]
R26  4.75K,1%  [402]
R27  0,1%  [402]
R28  33  [0402]
R45  22  [0402]
R46  0  [0402]
R47  0  [0402]
R48  0  [0402]
R49  0,1%  [402]
R50  0,1%  [402]
R51  0,1%  [402]
R52  10K,1%  [402]
R53  10K,1%  [402]
R159  0,1%  [402]
R163  4.75K,1%  [402]
R164  4.75K,1%  [402]
R165  100K,1%  [402]
TP9  TESTPT1  [TP60C33D]
U8  TPS2051 (DGN)  [DGN-16X60]
U9  TPD4S012  [U_6_DRY]
U10  TPD4S012  [U_6_DRY]
U15  SN74LVC2G241  [U_8_DCU]
sheet P05_AM335x 3/3
C37  0.1uf,6.3V  [402]
C38  0.1uf,6.3V  [402]
C39  10uF,10V  [805]
C40  10uF,10V  [805]
C41  0.1uf,6.3V  [402]
C42  0.1uf,6.3V  [402]
C43  0.1uf,6.3V  [402]
C44  0.1uf,6.3V  [402]
C45  0.1uf,6.3V  [402]
C46  0.1uf,6.3V  [402]
C47  0.1uf,6.3V  [402]
C48  0.1uf,6.3V  [402]
C49  0.1uf,6.3V  [402]
C50  0.1uf,6.3V  [402]
C51  0.1uf,6.3V  [402]
C52  0.1uf,6.3V  [402]
C53  0.1uf,6.3V  [402]
C54  0.1uf,6.3V  [402]
C55  10uF,10V  [805]
C56  0.1uf,6.3V  [402]
C57  0.1uf,6.3V  [402]
C58  0.1uf,6.3V  [402]
C59  0.1uf,6.3V  [402]
C60  0.1uf,6.3V  [402]
C61  0.1uf,6.3V  [402]
C62  10uF,10V  [805]
C63  0.1uf,6.3V  [402]
C64  0.1uf,6.3V  [402]
C65  0.1uf,6.3V  [402]
C66  0.1uf,6.3V  [402]
C67  0.1uf,6.3V  [402]
C68  0.1uf,6.3V  [402]
C69  0.1uf,6.3V  [402]
C70  0.1uf,6.3V  [402]
C71  0.1uf,6.3V  [402]
C72  0.1uf,6.3V  [402]
C73  0.1uf,6.3V  [402]
C74  0.1uf,6.3V  [402]
C75  0.1uf,6.3V  [402]
C76  0.1uf,6.3V  [402]
C77  10uF,10V  [805]
C78  0.1uf,6.3V  [402]
C79  0.1uf,6.3V  [402]
C80  0.1uf,6.3V  [402]
C81  0.1uf,6.3V  [402]
C82  0.1uf,6.3V  [402]
C83  0.1uf,6.3V  [402]
C84  0.1uf,6.3V  [402]
C85  0.1uf,6.3V  [402]
C86  0.1uf,6.3V  [402]
C87  0.1uf,6.3V  [402]
C88  0.1uf,6.3V  [402]
C89  1uF,10V  [402]
C90  1uF,10V  [402]
C91  1uF,10V  [402]
C92  0.1uf,6.3V  [402]
C93  0.1uf,6.3V  [402]
C94  0.1uf,6.3V  [402]
C95  10uF,10V  [805]
C96  10uF,10V  [805]
C97  0.1uf,6.3V  [402]
C98  0.1uf,6.3V  [402]
C99  0.1uf,6.3V  [402]
C100  0.1uf,6.3V  [402]
C101  0.1uf,6.3V  [402]
C102  0.1uf,6.3V  [402]
C103  0.1uf,6.3V  [402]
C104  1uF,10V  [402]
C105  0.1uf,6.3V  [402]
C106  1uF,10V  [402]
FB1  150OHM800mA  [sm-7351-ind-0805]
FB2  150OHM800mA  [sm-7351-ind-0805]
FB3  150OHM800mA  [sm-7351-ind-0805]
R54  10K,1%  [402]
TP2  TESTPT1  [TP60C_SMD]
TP3  TESTPT1  [TP60C_SMD]
U5  AM3358BZCZ100  [am33xx_15x15]  (sections A,B,C)
sheet P06_LED, Config
D2  LTST-C191TBKT  [LED_0603]
D3  LTST-C191TBKT  [LED_0603]
D4  LTST-C191TBKT  [LED_0603]
D5  LTST-C191TBKT  [LED_0603]
Q1  DMC56404  [SMini6-F3-B]  (sections A,B)
Q2  DMC56404  [SMini6-F3-B]  (sections A,B)
R55  100K,1%,DNI  [402]
R56  100K,1%  [402]
R57  100K,1%,DNI  [402]
R58  100K,1%,DNI  [402]
R59  100K,1%,DNI  [402]
R60  100K,1%,DNI  [402]
R61  100K,1%,DNI  [402]
R62  100K,1%,DNI  [402]
R63  100K,1%,DNI  [402]
R64  100K,1%,DNI  [402]
R65  100K,1%  [402]
R66  100K,1%  [402]
R67  100K,1%  [402]
R68  100K,1%  [402]
R69  100K,1%,DNI  [402]
R70  100K,1%,DNI  [402]
R71  4.75K,5%  [402]
R72  4.75K,5%  [402]
R73  4.75K,5%  [402]
R74  4.75K,5%  [402]
R75  100,1%  [402]
R76  100K,1%  [402]
R77  100K,1%  [402]
R78  100K,1%  [402]
R79  100K,1%  [402]
R80  100K,1%  [402]
R81  100K,1%,DNI  [402]
R82  100K,1%  [402]
R83  100K,1%  [402]
R84  100K,1%  [402]
R85  100K,1%  [402]
R86  100K,1%  [402]
R87  100K,1%  [402]
R88  100K,1%  [402]
R89  100K,1%  [402]
R90  100K,1%,DNI  [402]
R91  100K,1%,DNI  [402]
R92  100K,1%,DNI  [402]
R93  100K,1%,DNI  [402]
R94  100K,1%  [402]
R95  100K,1%  [402]
S2  KMR231GLFS  [SW4SMD_63X161LS]
sheet P07_DDR3 Memory
C107  0.1uf,6.3V  [402]
C108  0.1uf,6.3V  [402]
C109  0.1uf,6.3V  [402]
C110  0.1uf,6.3V  [402]
C111  0.1uf,6.3V  [402]
C112  0.1uf,6.3V  [402]
C113  0.1uf,6.3V  [402]
C114  0.1uf,6.3V  [402]
C115  0.1uf,6.3V  [402]
C116  0.1uf,6.3V  [402]
C117  0.1uf,6.3V  [402]
C118  10uF,10V  [805]
C119  0.1uf,6.3V  [402]
C120  0.1uf,6.3V  [402]
C121  0.1uf,6.3V  [402]
C122  10uF,10V  [805]
C123  0.001uf,50V  [402]
C124  0.1uf,6.3V  [402]
R96  10K,1%  [402]
R97  1.5K,1%  [402]
R98  10K,1%  [402]
R99  240  [SM-7351-RES-0402]
R100  10K,1%  [402]
U12  MT41K256M16HA -125:E  [BGA96_T9_P8_9X14]
sheet P08_eMMC FLASH
C125  2.2uF,6.3V  [402]
C126  10uF,10V  [805]
C127  0.1uf,6.3V  [402]
C128  0.1uf,6.3V  [402]
C129  0.1uf,6.3V  [402]
C130  0.1uf,6.3V  [402]
R101  10K,1%  [402]
R102  10K,1%  [402]
R103  10K,1%  [402]
R104  10K,1%  [402]
R105  10K,1%  [402]
R106  10K,1%  [402]
R107  10K,1%  [402]
R108  10K,1%  [402]
R109  10K,1%  [402]
R110  10K,1%  [402]
R111  10K,1%  [402]
U13  MEM_MNAND_2GB  [BGA153_P14_P5_11P5X13]
sheet P09_10/100 Ethernet
C131  0.1uf,6.3V  [402]
C132  0.1uf,6.3V  [402]
C133  10uF,10V  [805]
C134  1uF,10V  [402]
C135  0.1uf,6.3V  [402]
C136  470pF,6.3V  [0402]
C137  15pF,DNI  [402]
C138  15pF,DNI  [402]
C139  15pF,DNI  [402]
C140  15pF,DNI  [402]
C141  0.022uF,10V  [402]
C142  30pF,50V  [402]
C143  30pF,50V  [402]
FB4  150OHM800mA  [sm-7351-ind-0805]
P5  LPJ0011BBNL  [RJ45-7499010211A]
R112  1.5K,1%  [402]
R113  1.5K,1%  [402]
R114  1.5K,1%  [402]
R115  10K,1%  [402]
R116  10K,1%  [402]
R117  10K,1%  [402]
R118  10K,1%  [402]
R119  1.5K,1%  [402]
R120  49.9,1%  [402]
R121  49.9,1%  [402]
R122  49.9,1%  [402]
R123  49.9,1%  [402]
R124  10,1%,DNI  [402]
R125  100,1%  [402]
R126  100,1%  [402]
R127  100,1%  [402]
R128  100,1%  [402]
R129  100,1%  [402]
R130  470,5%  [402]
R131  100,1%  [402]
R132  470,5%  [402]
R133  100,1%  [402]
R134  100,1%  [402]
R135  10K,1%  [402]
R136  .1,0805  [805]
R137  0,1%  [402]
R138  100,1%  [402]
R139  100,1%  [402]
R140  0,1%,DNI  [402]
R141  1M,1%,DNI  [402]
R142  0,1%  [402]
R143  10,1%  [402]
R144  12.1K,1%  [402]
R145  10K,1%  [402]
U14  LAN8710A  [QFN32_5X5MM_EP3P3MM]
Y3  25.000MHz  [XTAL150SMD_125X196]
sheet P10_HDMI
C144  2.2uF,6.3V  [402]
C145  0.1uf,6.3V  [402]
C146  2.2uF,6.3V  [402]
C147  0.1uf,6.3V  [402]
C148  2.2uF,6.3V  [402]
C149  0.1uf,6.3V  [402]
C150  0.1uf,6.3V  [402]
C151  2.2uF,6.3V  [402]
C156  47pf,6.3V  [402]
C157  47pf,6.3V  [402]
C160  47pf,6.3V  [402]
C161  47pf,6.3V  [402]
C162  47pf,6.3V  [402]
C163  47pf,6.3V  [402]
C164  47pf,6.3V  [402]
C165  47pf,6.3V  [402]
C166  47pf,6.3V  [402]
C167  47pf,6.3V  [402]
C168  47pf,6.3V  [402]
C169  47pf,6.3V  [402]
C170  47pf,6.3V  [402]
C171  47pf,6.3V  [402]
C172  47pf,6.3V  [402]
C173  47pf,6.3V  [402]
D6  IP4283CZ10-TT  [TSSOP10]
D7  IP4283CZ10-TT  [TSSOP10]
D8  RB751V40,115  [SOD323]
FB5  150OHM800mA  [sm-7351-ind-0805]
P6  10118241-001RLF  [CONN19_HDMI]
R146  1.5K,1%  [402]
R147  1.5K1%  [402]
R148  10K,1%  [402]
R149  0,1%  [402]
R158  10K,1%  [402]
R166  27K,1%  [402]
RT1  PTC_RXEF010  [polysw200-5638-310]
U11  TDA19988  [QFN64S9X9P5]
sheet P11_Exp Conn, uSD
C152  0.1uf,6.3V  [402]
C153  10uF,10V  [805]
C154  0.1uf,6.3V  [402]
P8  FEMALE HEADER 2x23  [HEADER23X2]
P9  FEMALE HEADER 2x23  [HEADER23X2]
P10  SCHA5B0200  [SD-MICRO-SCHA5B0300]
R150  10K,1%  [402]
R151  10K,1%  [402]
R152  10K,1%  [402]
R153  10K,1%  [402]
R154  10K,1%  [402]
R155  10K,1%  [402]
R156  10K,1%  [402]
R157  10K,1%  [402]
TP4  TESTPT1  [tp1-8040]
U7  24LC32A  [SOT23-5]

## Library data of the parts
C1 C2 C4 C7-C15 C39 C40 C55 C62 C77 C95 C96 C118 C122 C126 C133 C153 = CAP_10uF_Y5V_10V_10%_0805
C3 C20 C27-C31 C33 C35-C38 C41-C54 C56-C61 C63-C76 C78-C88 C92-C94 C97-C103 C105 C107-C117 C119-C121 C124 C127-C132 C135 C145 C147 C149 C150 C152 C154-C173 = CAP_0.1uF_X5R_6.3V_20%_0201
C16-C18 C125 C144 C146 C148 C151 = CAP_2.2uF_X5R_6.3V_10%_0402
C19 = CAP_470PF_X7R_25V_10%_0402
D1-D5 = LED_LTST-C150GKT_0
L1-L3 = IND_2.2uH_2.6A_10%_SMD
MTG1-MTG4 = MHOLE
P1 = Power_Jack
R1 R49 R55-R70 R75-R95 R165 = RES_100K_1_16W_1%_0402
R3 R4 R119 R146 R147 = RES_1.5K_1_16W_5%_0402
R5-R9 R23-R26 R50 R51 R112-R118 R159-R164 = RES_4.75K_1_16W_1%_0402
R10-R12 R71-R74 R130 R132 = RES_470_1_10W_5%_0402
S1 S3 = SW_KT11P2JM_2
TP1-TP9 = TESTPT1
U2 = PWR_TPS65217_2
U4 = PWR_TLV70233DBV_0
C21 C22 C25 C26 = CAP_18PF_COG_50V_5%_0402
C24 C89-C91 C104 C106 C134 = CAP_1.0UF_X5R_10V_10%_0402
P2 = HDR_10x2_CJTAG_0
R14 R52-R54 R96-R98 R100-R111 R135 R137 R143 R145 R148 R150-R155 R157 R158 = RES_10K_1_16W_1%_0402
R17 R141 = RES_1M_1_16W_1%_0402
R18 R21 R28 R45-R48 R167 = RES_33_0402: Part Number: RES_33_0201
R19 R20 R27 R29 R30 R140 R142 R149 R156 = RES_0_1_16W_1%_0402
R22 R120-R123 = RES_4.7K_0402
U3 = IC_SN74LVC1G06DCK_0
U6 = IC_SN74AUC1G74
U16 = IC_SN74LVC1G07DCK
Y1 = CRYS_32_768KHz_SMD32_1
Y2 = CRYS_24MHz_SCC_0
Y4 = OSC_12MHz_1.3V
C32 C123 = CAP_0.001_X7R_50V_5%_0402
C34 = CAP_100UF_TANT_6.3V_3528-21
FB1-FB4 FB7 FB8 = FER_180_200_0
J1 = HEADER_6
P3 = CONN_54819-0578_2
P4 = MINI-USB-AB-SOCKET
U8 = TPS2061_1
U9 U10 = PROT_TPD4S012
U15 = IC_SN74LVC2G241_1
U5 = IC_AM335X_ZCZ
Q1 Q2 = RN1907: ATLStockNo2: 2130.01
S2 = SW_KT11P2JM_1
R99 = Res: Res, 240E, 1%, Thick Film, 0.1W, SMD, Size 0402; Created By: Sankar; Created Date: 4/12/2010; DescriptiveText: RES 240 OHM 1/10W 1% 0402 SMD; Mfg: KOA; Mfr: Panasonic-ECG; MfrNum: ERJ-2RKF2400X; PartName: 240E1/10W1%smd0402; Sub_Type: Thick Film; Tolerance: 1%
U12 = MT47H256M8_7: DescriptiveText: DDR3 Memory 4Gb; Mfr: Micron; MfrNum: MT41J256M16RE-15E; PartName: MT41J256M16RE-15E
U13 = MEM_MNAND_2GB
C136 = 470pF_5%_50V_C0G_0603_0
C137-C140 = CAP_0402_100pF_COG_50V
C141 = CAP_0402_0.1uf_X5R_10V
C142 C143 = CAP_30PF_COG_50V_5%_0402
P5 = CONN_RJ45_MAG_WE_0
R124-R126 R129 R134 R138 = 100-1_10W-1%-0603_4
R127 R128 R131 R133 R139 = RES_100_1_10W_5%_0402
R136 = RES_0.1_0805
R144 = RES_12.1K_1_16W_1%_0402
U14 = LAN8710_QFN32_1
Y3 = Suntsu_ITEMP_25MHz__0.005%_20pf
D6 D7 = 32CTQ030_TO_1
D8 = DIO_SR305_TH_0
FB5 = FER_180_200_0805
P6 = CONN_HDMI_TYPED
R166 = RES_22.6K_1_16W_1%_0402
RT1 = PTC_RXEF010
U11 = IC_TDA19988_HVQFN64_5
P8 P9 = HDR_46_F_2_0.1_0.1
P10 = microSD_CONN_8
U7 = MEM_24LC32_SOT23-5

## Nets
DGND: C1.1 C2.1 C3.1 C4.1 C7.1 C8.1 C9.1 C10.1 C11.1 C12.1 C13.1 C14.1 C15.1 C16.2 C17.2 C18.2 C19.2 C20.2 C24.2 C27.2 C28.2 C29.2 C30.2 C34.2 C35.2 C36.2 C37.2 C38.2 C39.1 C40.1 C41.2 C42.2 C43.2 C44.2 C45.2 C46.2 C47.2 C48.2 C49.2 C50.2 C51.2 C52.2 C53.2 C54.2 C55.1 C56.1 C57.1 C58.2 C59.2 C60.1 C61.1 C62.1 C63.2 C64.2 C65.2 C66.2 C67.2 C68.1 C69.1 C70.1 C71.1 C72.1 C73.1 C74.1 C75.1 C76.1 C77.2 C78.2 C79.2 C80.2 C81.2 C82.2 C83.2 C84.2 C85.2 C86.2 C87.2 C88.2 C89.2 C90.2 C91.2 C92.2 C94.2 C95.1 C96.1 C97.2 C98.2 C99.2 C100.2 C101.2 C102.2 C103.2 C104.2 C105.2 C106.2 C107.2 C108.2 C109.2 C110.2 C111.2 C112.2 C113.2 C114.2 C115.2 C116.2 C117.2 C118.1 C119.2 C120.2 C121.2 C122.1 C123.2 C124.2 C125.2 C126.1 C127.2 C128.2 C129.2 C130.2 C131.2 C132.2 C133.1 C134.2 C135.2 C136.2 C137.2 C138.2 C139.2 C140.2 C141.2 C142.2 C143.2 C144.2 C145.2 C146.2 C147.2 C148.2 C149.2 C150.2 C151.2 C152.2 C153.2 C154.2 C155.1 C156.2 C157.2 C158.2 C159.2 C160.2 C161.2 C162.2 C163.2 C164.2 C165.2 C166.2 C167.2 C168.2 C169.2 C170.2 C171.2 C172.2 C173.2 D6.3 D6.8 D7.3 D7.8 FB3.2 J1.1 P1.2 P2.4(TDIS) P2.8(GND1) P2.10(GND2) P2.12(GND3) P2.16(GND4) P2.20(GND5) P3.4(P4) P4.5(G1) P5.8(GND) P6.4(DAT2_S) P6.7(DAT1_S) P6.10(DAT0_S) P6.13(CLK_S) P6.16(DDC/CEC_GND) P8.1 P8.2(26) P9.1 P9.2(26) P9.43(22) P9.44(47) P9.45(23) P9.46(48) P10.6(VSS) P10.9(GND) Q1.1(4) Q1.4 Q2.1(4) Q2.4 R10.2 R12.1 R22.1 R25.2 R29.2 R49.1 R53.2 R54.1 R76.2 R77.2 R78.2 R79.2 R80.2 R81.2 R82.2 R83.2 R84.2 R85.2 R86.2 R87.2 R88.2 R89.2 R90.2 R91.2 R92.2 R93.2 R94.2 R95.2 R96.1 R99.1 R100.2 R115.2 R116.2 R117.2 R118.2 R130.1 R132.1 R135.2 R136.1 R144.2 R145.2 R148.2 R149.2 R164.2 R165.2 S1.1(A1) S1.3(A2) S2.2(B1) S2.4(B2) S3.1(A1) S3.3(A2) TP1.1(TP) TP8.1(TP) U2.30(PGND) U2.41(AGND) U2.49(PPAD) U3.3(GND) U4.5(GND1) U4.6(GND3) U4.7(GND2) U4.8(GND4) U5.A1(VSS1) U5.A18(VSS2) U5.F8(VSS3) U5.G8(VSS4) U5.G9(VSS5) U5.G11(VSS6) U5.G12(VSS7) U5.H6(VSS8) U5.H7(VSS9) U5.H8(VSS10) U5.H9(VSS11) U5.H10(VSS12) U5.H12(VSS13) U5.J6(VSS14) U5.J7(VSS15) U5.J8(VSS16) U5.J9(VSS17) U5.J10(VSS18) U5.J11(VSS19) U5.K7(VSS20) U5.K9(VSS21) U5.K10(VSS22) U5.K11(VSS23) U5.L10(VSS24) U5.L11(VSS25) U5.L12(VSS26) U5.L13(VSS27) U5.M6(VSS28) U5.M7(VSS29) U5.M8(VSS30) U5.M9(VSS31) U5.M10(VSS32) U5.M12(VSS33) U5.M14(VSSA_USB2) U5.N7(VSS34) U5.N10(VSS35) U5.N11(VSS36) U5.N14(VSSA_USB1) U5.V1(VSS37) U5.V18(VSS38) U6.4(GND) U7.2(VSS) U8.1(GND) U8.9(PAD) U9.4(GND) U10.4(GND) U11.8(VPB1) U11.9(VPB0) U11.16(VPC2) U11.17(VPC1) U11.18(VPC0) U11.19(VPP) U11.53(A0_I2C) U11.54(A1_I2C) U11.61(VPA2) U11.62(VPA1) U11.63(VPA0) U11.65(PAD) U12.A9(VSS1) U12.B1(VSSQ1) U12.B3(VSS2) U12.B9(VSSQ2) U12.D1(VSSQ3) U12.D8(VSSQ4) U12.E1(VSS3) U12.E2(VSSQ5) U12.E8(VSSQ6) U12.F9(VSSQ7) U12.G1(VSSQ8) U12.G8(VSS4) U12.G9(VSSQ9) U12.J2(VSS5) U12.J8(VSS6) U12.M1(VSS7) U12.M9(VSS8) U12.P1(VSS9) U12.P9(VSS10) U12.T1(VSS11) U12.T9(VSS12) U13.C4(VSSQ4) U13.E7(VSS2) U13.G5(VSS1) U13.H10(VSS3) U13.K8(VSS4) U13.N2(VSSQ1) U13.N5(VSS5) U13.P4(VSSQ3) U13.P6(VSSQ2) U14.33(GND_EP) U15.1(~{1OE}) U15.4(GND) U16.3(GND) Y4.2(GND)
GND_EARTH: MTG1.1(TP) MTG2.1(TP) MTG3.1(TP) MTG4.1(TP) P3.5(SHELD1) P3.6(PAD4) P4.6(G3) P4.7(G2) P4.8(G5) P4.9(G4) P5.13(SHD1) P5.14(SHD2) P6.20(MTG1) P6.21(MTG2) P6.22(MTG3) P6.23(MTG4) P10.11(GND3) P10.12(GND4) P10.13(GND5) P10.14(GND6) P10.15(GND7) P10.16(GND8) R136.2
GND_OSC0: C25.2 C26.2 R29.1 R30.1 U5.V11(VSS_OSC0)
GND_OSC1: C21.1 C22.1 R30.2 U5.A5(VSS_RTC)
GNDA_ADC: C31.2 C32.2 C33.2 C93.2 FB3.1 P9.34(42) U5.A9(VREFN) U5.E8(VSSA_ADC)
VBUS: FB7.2 P3.1(P1)
VDD_1V8: C14.2 C78.1 C86.1 C88.1 FB1.1 FB2.2 FB5.2 R9.2 U2.40(LDO3) U5.D10(VDDS_SRAM_MPU_BB) U5.E9(VDDS_SRAM_CORE_BG) U5.N16(VDDA1P8V_USB0) U5.R16(VDDA1P8V_USB1)
VDD_3V3A: C15.2 C27.1 C37.1 C38.1 C56.2 C57.2 C58.1 C59.1 C60.2 C61.2 C66.1 C67.1 C68.2 C69.2 C70.2 C71.2 C72.2 C73.2 C74.2 C75.2 C76.2 C77.1 C87.1 C152.1 C158.1 C159.1 R1.1 R3.1 R4.1 R14.1 R52.1 R55.1 R56.1 R57.1 R58.1 R59.1 R60.1 R61.1 R62.1 R63.1 R64.1 R65.1 R66.1 R67.1 R68.1 R69.1 R70.1 R156.1 U2.43(LDO4) U3.5(VCC) U4.1(EN) U5.E10(VDDSHV61) U5.E11(VDDSHV62) U5.E12(VDDSHV63) U5.E13(VDDSHV64) U5.F14(VDDSHV65) U5.G14(VDDSHV66) U5.H14(VDDSHV41) U5.J14(VDDSHV42) U5.K14(VDDSHV51) U5.L14(VDDSHV52) U5.N5(VDDSHV67) U5.N15(VDDA3P3V_USB0) U5.P5(VDDSHV68) U5.P6(VDDSHV69) U5.P7(VDDSHV11) U5.P8(VDDSHV12) U5.P10(VDDSHV21) U5.P11(VDDSHV22) U5.P12(VDDSHV31) U5.P13(VDDSHV32) U5.R15(VDDA3P3V_USB1) U6.6(~{CLR}) U6.7(~{PRE}) U6.8(VCC) U7.4(VCC) Y4.4(VCC)
VDD_3V3AUX: C18.1 D1.2(A) U2.1(VLDO2)
VDD_3V3B: C20.1 C29.1 C126.2 C127.1 C128.1 C129.1 C130.1 C135.1 C153.1 C154.1 C155.2 FB4.1 P2.5(TVDD) P9.3(2) P9.4(27) P10.4(VDD) R11.1 R23.1 R24.1 R101.1 R102.1 R103.1 R104.1 R105.1 R106.1 R107.1 R108.1 R109.1 R110.1 R111.1 R112.2 R113.2 R114.2 R119.1 R150.1 R151.1 R152.1 R153.1 R154.1 R155.1 R157.2 R158.1 R163.1 R166.2 U4.3(OUT) U13.C6(VCCQ4) U13.E6(VCC3) U13.F5(VCC2) U13.J10(VCC0) U13.K9(VCC1) U13.M4(VCCQ5) U13.N4(VCCQ3) U13.P3(VCCQ1) U13.P5(VCCQ2) U14.12(VDDIO) U15.7(2OE) U15.8(VCC)
VDD_5V: C2.2 P1.1 P9.5(3) P9.6(28) U2.10(AC)
VDD_ADC: C93.1 FB2.1 P9.32(41) R27.1 U5.D8(VDDA_ADC)
VDD_CORE: C11.2 C39.2 C40.2 C41.1 C42.1 C43.1 C44.1 C45.1 C46.1 C47.1 C48.1 C49.1 C50.1 C51.1 C52.1 C53.1 C54.1 C55.2 L3.2 U2.29(VDCDC3) U5.F6(VDD_CORE1) U5.F7(VDD_CORE2) U5.G6(VDD_CORE3) U5.G7(VDD_CORE4) U5.G10(VDD_CORE5) U5.H11(VDD_CORE6) U5.J12(VDD_CORE7) U5.K6(VDD_CORE8) U5.K8(VDD_CORE9) U5.K12(VDD_CORE10) U5.L6(VDD_CORE11) U5.L7(VDD_CORE12) U5.L8(VDD_CORE13) U5.L9(VDD_CORE14) U5.M11(VDD_CORE15) U5.M13(VDD_CORE16) U5.N8(VDD_CORE17) U5.N9(VDD_CORE18) U5.N12(VDD_CORE19) U5.N13(VDD_CORE20)
VDD_MPU: C12.2 C62.2 C63.1 C64.1 C65.1 L2.2 U2.24(VDCDC2) U5.F10(VDD_MPU1) U5.F11(VDD_MPU2) U5.F12(VDD_MPU3) U5.F13(VDD_MPU4) U5.G13(VDD_MPU5) U5.H13(VDD_MPU6) U5.J13(VDD_MPU7)
VDD_MPUON: TP2.1(TP) U5.A2(VDD_MPU_MON)
VDD_PHYA: C131.1 C132.1 C133.2 FB4.2 R120.2 R121.2 R122.2 R123.2 R137.2 U14.1(VDD2A) U14.27(VDD1A)
VDD_PLL: C79.1 C92.1 C94.1 C106.1 FB1.2 U5.E7(VDDS_PLL_DDR) U5.H15(VDDS_PLL_MPU) U5.R10(VDDS_PLL_CORE_LCD) U5.R11(VDDS_OSC)
VDD_RTC: C104.1 U5.D6(CAP_VDD_RTC)
VDDS: C80.1 C81.1 C82.1 C83.1 C84.1 C85.1 R8.2 R9.1 U5.E6(VDDS1) U5.E14(VDDS2) U5.F9(VDDS3) U5.K13(VDDS4) U5.N6(VDDS5) U5.P9(VDDS6) U5.P14(VDDS7)
VDDS_DDR: C9.2 C95.2 C96.2 C97.1 C98.1 C99.1 C100.1 C101.1 C102.1 C103.1 C107.1 C108.1 C109.1 C110.1 C111.1 C112.1 C113.1 C114.1 C115.1 C116.1 C117.1 C118.2 C119.1 C120.1 C121.1 C122.2 R6.2 R97.1 R98.1 U5.E5(VDDS_DDR1) U5.F5(VDDS_DDR2) U5.G5(VDDS_DDR3) U5.H5(VDDS_DDR4) U5.J5(VDDS_DDR5) U5.K5(VDDS_DDR6) U5.L5(VDDS_DDR7) U12.A1(VDDQ1) U12.A8(VDDQ2) U12.B2(VDD1) U12.C1(VDDQ3) U12.C9(VDDQ4) U12.D2(VDDQ5) U12.D9(VDD9) U12.E9(VDDQ7) U12.F1(VDDQ8) U12.G7(VDD2) U12.H2(VDDQ9) U12.H9(VDDQ10) U12.K2(VDD4) U12.K8(VDD5) U12.N1(VDD6) U12.N9(VDD7) U12.R1(VDD8) U12.R9(VDD3)
12M_LOOP: U6.2(D) U6.3(~{Q})
12MHZ: R21.2 U11.27(OSC_IN)
AIN0: P9.39(20) U5.B6(AIN0)
AIN1: P9.40(45) U5.C7(AIN1)
AIN2: P9.37(19) U5.B7(AIN2)
AIN3: P9.38(44) U5.A7(AIN3)
AIN4: P9.33(17) U5.C8(AIN4)
AIN5: P9.36(43) U5.B8(AIN5)
AIN6: P9.35(18) U5.A8(AIN6)
AIN7: R163.2 R164.1 U5.C9(AIN7)
B_UART0_RX: J1.4 R165.1 U15.2(1A)
B_UART0_TX: J1.5 U15.3(2Y)
CAP_VBB_MPU: C91.1 U5.C10(CAP_VBB_MPU)
CAP_VDD_SRAM_CORE: C89.1 U5.D9(CAP_VDD_SRAM_CORE)
CAP_VDD_SRAM_MPU: C90.1 U5.D11(CAP_VDD_SRAM_MPU)
CLKOUT2: P2.18(EMU3) P9.41(21) R19.2 R20.1
CLKOUT_SRC: R19.1 U5.D14(EVENT_INTR1/TCLKIN/CLKOUT2/TIMER7/PR1PRU0_PRUR31_16/EMU3/GPIO0_20)
CRS: R139.2 U14.14(CRS)
DDR_A0: U5.F3(DDR_A0) U12.N3(A0)
DDR_A1: U5.H1(DDR_A1) U12.P7(A1)
DDR_A2: U5.E4(DDR_A2) U12.P3(A2)
DDR_A3: U5.C3(DDR_A3) U12.N2(A3)
DDR_A4: U5.C2(DDR_A4) U12.P8(A4)
DDR_A5: U5.B1(DDR_A5) U12.P2(A5)
DDR_A6: U5.D5(DDR_A6) U12.R8(A6)
DDR_A7: U5.E2(DDR_A7) U12.R2(A7)
DDR_A8: U5.D4(DDR_A8) U12.T8(A8)
DDR_A9: U5.C1(DDR_A9) U12.R3(A9)
DDR_A10: U5.F4(DDR_A10) U12.L7(A10)
DDR_A11: U5.F2(DDR_A11) U12.R7(A11)
DDR_A12: U5.E3(DDR_A12) U12.N7(A12)
DDR_A13: U5.H3(DDR_A13) U12.T3(A13)
DDR_A14: U5.H4(DDR_A14) U12.T7(A14)
DDR_A15: U5.D3(DDR_A15) U12.M7(A15)
DDR_BA0: U5.C4(DDR_BA0) U12.M2(BA0)
DDR_BA1: U5.E1(DDR_BA1) U12.N8(BA1)
DDR_BA2: U5.B3(DDR_BA2) U12.M3(BA2)
DDR_CASn: U5.F1(DDR_CASN) U12.K3(CASn)
DDR_CKE: R96.2 U5.G3(DDR_CKE) U12.K9(CKE)
DDR_CLK: U5.D2(DDR_CK) U12.J7(CK)
DDR_CLKn: U5.D1(DDR_NCK) U12.K7(CKn)
DDR_CSn: U5.H2(DDR_CSN0) U12.L2(CSn)
DDR_D0: U5.M3(DDR_D0) U12.E3(DQ0)
DDR_D1: U5.M4(DDR_D1) U12.F7(DQ1)
DDR_D2: U5.N1(DDR_D2) U12.F2(DQ2)
DDR_D3: U5.N2(DDR_D3) U12.F8(DQ3)
DDR_D4: U5.N3(DDR_D4) U12.H3(DQ4)
DDR_D5: U5.N4(DDR_D5) U12.H8(DQ5)
DDR_D6: U5.P3(DDR_D6) U12.G2(DQ6)
DDR_D7: U5.P4(DDR_D7) U12.H7(DQ7)
DDR_D8: U5.J1(DDR_D8) U12.D7(DQ8)
DDR_D9: U5.K1(DDR_D9) U12.C3(DQ9)
DDR_D10: U5.K2(DDR_D10) U12.C8(DQ10)
DDR_D11: U5.K3(DDR_D11) U12.C2(DQ11)
DDR_D12: U5.K4(DDR_D12) U12.A7(DQ12)
DDR_D13: U5.L3(DDR_D13) U12.A2(DQ13)
DDR_D14: U5.L4(DDR_D14) U12.B8(DQ14)
DDR_D15: U5.M1(DDR_D15) U12.A3(DQ15)
DDR_DQM0: U5.M2(DDR_DQM0) U12.E7(LDM)
DDR_DQM1: U5.J2(DDR_DQM1) U12.D3(UDM)
DDR_DQS0: U5.P1(DDR_DQS0) U12.F3(LDQS)
DDR_DQS1: U5.L1(DDR_DQS1) U12.C7(UDQS)
DDR_DQSN0: U5.P2(DDR_DQSN0) U12.G3(LDQSn)
DDR_DQSN1: U5.L2(DDR_DQSN1) U12.B7(UDQSn)
DDR_ODT: U5.G1(DDR_ODT) U12.K1(ODT)
DDR_RASn: U5.G4(DDR_RASN) U12.J3(RASn)
DDR_RESETn: R97.2 U5.G2(DDR_RESETN) U12.T2(RESET#)
DDR_VREF: C28.1 C123.1 C124.1 R98.2 R100.1 U5.J4(VREFSSTL) U12.H1(VREF_DQ) U12.M8(VREF_CA)
DDR_VTP: R22.2 U5.J3(DDR_VTP)
DDR_WEn: U5.B2(DDR_WEn) U12.L3(WEn)
DVI_+5V: P6.19(+5V) R146.1 R147.1 RT1.2
EHRPWM1A: P9.14(32) U5.U14(GPMC_A2/GMII2_TXD3/RGMII2_TD3/MMC2_DAT1/GPMC_A18/PR1_MII1_TXD2/EHRPWM1A/GPIO1_18)
EHRPWM1B: P9.16(33) U5.T14(GPMC_A3/GMII2_TXD2/RGMII2_TD2/MMC2_DAT2/GPMC_A19/PR1_MII1_TXD1/EHRPWM1B/GPIO1_19)
EHRPWM2A: P8.19(10) U5.U10(GPMC_AD8/LCD_DATA23/MMC1_DAT0/MMC2_DAT4/EHRPWM2A/PR1_MII_MT0_CLK//GPIO0_22)
EHRPWM2B: P8.13(7) U5.T10(GPMC_AD9/LCD_DATA22/MMC1_DAT1/MMC2_DAT5/EHRPWM2B/PR1_MII0_CRS//GPIO0_23)
eMMC_RSTn: R111.2 R162.2 U13.K5(~{RST})
eMMC_VCCI: C125.1 U13.C2(VCCI)
ENZ_KALDO_1P8V: R54.2 U5.B4(ENZ_KALDO_1P8V)
ETH_TXD4: R145.1 U14.18(nINT/TXER/TXD4)
GPIO0_7: P9.42(46) R50.1 R51.1
GPIO0_7SRC: R50.2 U5.C18(ECAP0_IN_PWM0_OUT/UART3_TXD/SPI1_CS1/PR1_ECAP0_ECAP_CAPIN_APWM_O/SPI1_SCLK/MMC0_SDWP/XDMA_EVENT_INTR2/GPIO0_7)
GPIO0_26: P8.14(32) U5.T11(GPMC_AD10/LCD_DATA21/MMC1_DAT2/MMC2_DAT6/EHRPWM2_TRIPZONE_INPUT/PR1_MII0_TXEN//GPIO0_26)
GPIO0_27: P8.17(9) U5.U12(GPMC_AD11/LCD_DATA20/MMC1_DAT3/MMC2_DAT7/EHRPWM2_SYNCI_O/PR1_MII0_TXD3//GPIO0_27)
GPIO1_12: P8.12(31) U5.T12(GPMC_AD12/LCD_DATA19/MMC1_DAT4/MMC2_DAT0/EQEP2A_IN/PR1_MII0_TXD2/PR1_PRU0_PRU_R30_14/GPIO1_12)
GPIO1_13: P8.11(6) U5.R12(GPMC_AD13/LCD_DATA18/MMC1_DAT5/MMC2_DAT1/EQEP2B_IN/PR1_MII0_TXD1/PR1_PRU0_PRU_R30_15/GPIO1_13)
GPIO1_14: P8.16(33) U5.V13(GPMC_AD14/LCD_DATA17/MMC1_DAT6/MMC2_DAT2/EQEP2_INDEX/PR1_MII0_TXD0/PR1_PRU0_PRU_R31_14/GPIO1_14)
GPIO1_15: P8.15(8) U5.U13(GPMC_AD15/LCD_DATA16/MMC1_DAT7/MMC2_DAT3/EQEP2_STROBE/PR1_ECAP0_ECAP_CAPIN_APWM_O/PR1_PRU0_PRU_R31_15/GPIO1_15)
GPIO1_16: P9.15(8) R160.2 R161.2
GPIO1_17: P9.23(12) U5.V14(GPMC_A1/GMII2_RXDV/RGMII2_RCTL/MMC2_DAT0/GPMC_A17/PR1_MII1_TXD3/EHRPWM1_SYNCI_O/GPIO1_17)
GPIO1_28: P9.12(31) U5.U18(GPMC_BE1N/GMII2_COL/GPMC_CSN6/MMC2_DAT3/GPMC_DIR/PR1_MII1_RXLINK/MCASP0_ACLKR/GPIO1_28)
GPIO1_29: P8.26(38) U5.V6(GPMC_CSN0/GPIO1_29)
GPIO2_1: P8.18(34) U5.V12(GPMC_CLK/LCD_MEM_CLK/GPMC_WAIT1/MMC2_CLK/PRT1_MII1_TXEN/MCASP0_FSR/GPIO2_1)
GPIO3_18: R51.2 U5.B12(MCASP0_ACLKR/EQEP0A_IN/MCASP0_AXR2/MCASP1_ACLKX/MMC0_SDWP/PR1_PRU0_PRU_R30_4/PR1_PRU0_PRU_R31_4/GPIO3_18)
GPIO3_19: P9.27(14) U5.C13(MCASP0_FSR/EQEP0B_IN/MCASP0_AXR3/MCASP1_FSX/EMU2/PR1_PRU0_PRU_R30_5/PR1_PRU0_PRU_R31_5/GPIO3_19)
GPIO3_20: R20.2 U5.D13(MCASP0_AXR1/EQEP0_INDEX//MCASP1_AXR0/EMU3/PR1_PRU0_PRU_R30_6/PR1_PRU0_PRU_R31_6/GPIO3_20)
GPIO3_21: P9.25(13) R167.2 U5.A14(MCASP0_AHCLKX/EQEP0_STROBE/MCASP0_AXR3/MCASP1_AXR1/EMU4/PR1_PRU0_PRU_R30_7/PR1_PRU0_PRU_R31_7/GPIO3_21)
GRN_C: P5.10(GRNC) R132.2
GRNA: P5.9(GRNA) U14.3(LED1/REGOFF)
HDMI_1V8: C144.1 C145.1 C146.1 C147.1 C148.1 C149.1 C150.1 C151.1 FB5.1 U11.5(VDDDC0(1.8V)) U11.14(VDDIOA(1.8V)) U11.29(VDDDC1(1.8V)) U11.35(VDDA0(1.8V)) U11.36(VDDA1(TX)(1.8V)) U11.41(VDDA2(TX)(1.8V)) U11.46(VDDA3(TX)(1.8V)) U11.47(VDDA(PLL0)(1.8V)) U11.48(VDDA(PLL1)(1.8V)) U11.55(VDDIOB(1.8V))
HDMI_CEC: D8.1(CATHODE) P6.15(CEC) U11.30(CEC)
HDMI_CEC_D: D8.2(ANODE) R166.1
HDMI_DSCL: P6.17(SCL) R146.2 U11.33(DSCL)
HDMI_DSDA: P6.18(SDA) R147.2 U11.32(DSDA)
HDMI_HPD: P6.1(HPLG) U11.31(HPD)
HDMI_INT: R158.2 U5.U16(GPMC_A9/GMII2_RXD2/RGMII2_RD2/MMC2_DAT7/GPMC_A25/PR1_MII_MR1_CLK/MCASP0_FSX/GPIO1_25) U11.50(INT)
HDMI_SWING: R148.1 U11.34(EXT_SWING)
HDMI_TX0+: D6.2 P6.9(DAT0+) U11.40(TX0+)
HDMI_TX0-: D6.1 P6.11(DAT0-) U11.39(TX0-)
HDMI_TX1+: D7.5 P6.6(DAT1+) U11.43(TX1+)
HDMI_TX1-: D7.4 P6.8(DAT1-) U11.42(TX1-)
HDMI_TX2+: D7.2 P6.3(DAT2+) U11.45(TX2+)
HDMI_TX2-: D7.1 P6.5(DAT2-) U11.44(TX2-)
HDMI_TXC+: D6.4 P6.12(CLK+) U11.38(TXC+)
HDMI_TXC-: D6.5 P6.14(CLK-) U11.37(TXC-)
HDMICLK_DISn: U5.V17(GPMC_A11/GMII2_RXD0/RGMII2_RD0/RMII2_RXD0/GPMC_A27/PR1_MII1_RXER/MCASP0_AXR1/GPIO1_27) Y4.1(OE)
I2C0_SCL: R3.2 U2.28(SCL) U5.C16(I2C0_SCL/TIMER7/UART2_RTSN/ECAP1_IN_PWM1_OUT////GPIO3_6) U7.1(SCL) U11.52(CSCL)
I2C0_SDA: R4.2 U2.27(SDA) U5.C17(I2C0_SDA/TIMER4/UART2_CTSN/ECAP2_IN_PWM2_OUT////GPIO3_5) U7.3(SDA) U11.51(CSDA)
I2C1_SCL: P9.17(9) U5.A16(SPI0_CS0/MMC2_SDWP/I2C1_SCL/EHRPWM0_SYNCI_O/PR1_UART0_TXD/PR1_EDIO_DATA_IN1/PR1_EDIO_DATA_OUT1/GPIO0_5)
I2C1_SDA: P9.18(34) U5.B16(SPI0_D1/MMC1_SDWP/I2C1_SDA/EHRPWM0_TRIPZONE_INPUT/PR1_UART0_RXD/PR1_EDIO_DATA_IN0/PR1_EDIO_DATA_OUT0/GPIO0_4)
I2C2_SCL: P9.19(10) U5.D17(UART1_RTSN/TIMER5/DCAN0_RX/I2C2_SCL/SPI1_CS1/PR1_UART0_RTS_N/PR1_EDC_LATCH1_IN/GPIO0_13)
I2C2_SDA: P9.20(35) U5.D18(UART1_CTSN/TIMER6/DCAN0_TX/I2C2_SDA/SPI1_CS0/PR1_UART0_CTS_N/PR1_EDC_LATCH0_IN/GPIO0_12)
JTAG_EMU0: P2.13(EMU0) R23.2 U5.C14(EMU0/GPIO3_7)
JTAG_EMU1: P2.14(EMU1) R24.2 U5.B14(EMU1/GPIO3_8)
JTAG_TCK: P2.9(TCKRTN) P2.11(TCK) U5.A12(TCK)
JTAG_TDI: P2.3(TDI) U5.B11(TDI)
JTAG_TDO: P2.7(TDO) U5.A11(TDO)
JTAG_TMS: P2.1(TMS) U5.C11(TMS)
JTAG_TRSTn: P2.2(TRSTn) R25.1 U5.B10(NTRST)
LCD_DATA0: C173.1 P8.45(23) R70.2 R95.1 U5.R1(LCD_DATA0/GPMC_A0//EHRPWM2A//PR1_PRU1_PRU_R30_0/PR1_PRU1_PRU_R31_0/GPIO2_6) U11.15(VPC3)
LCD_DATA1: C171.1 P8.46(48) R69.2 R94.1 U5.R2(LCD_DATA1/GPMC_A1//EHRPWM2B//PR1_PRU1_PRU_R30_1/PR1_PRU1_PRU_R31_1/GPIO2_7) U11.13(VPC4)
LCD_DATA2: C172.1 P8.43(22) R68.2 R75.1 R93.1 U5.R3(LCD_DATA2/GPMC_A2//EHRPWM2_TRIPZONE_INPUT//PR1_PRU1_PRU_R30_2/PR1_PRU1_PRU_R31_2/GPIO2_8) U11.12(VPC5)
LCD_DATA3: C170.1 P8.44(47) R67.2 R92.1 U5.R4(LCD_DATA3/GPMC_A3//EHRPWM2_SYNCI_O//PR1_PRU1_PRU_R30_3/PR1_PRU1_PRU_R31_3/GPIO2_9) U11.11(VPC6)
LCD_DATA4: C169.1 P8.41(21) R66.2 R91.1 U5.T1(LCD_DATA4/GPMC_A4//EQEP2A_IN//PR1_PRU1_PRU_R30_4/PR1_PRU1_PRU_R31_4/GPIO2_10) U11.10(VPC7)
LCD_DATA5: C163.1 P8.42(46) R65.2 R90.1 U5.T2(LCD_DATA5/GPMC_A5//EQEP2B_IN//PR1_PRU1_PRU_R30_5/PR1_PRU1_PRU_R31_5/GPIO2_11) U11.7(VPB2)
LCD_DATA6: C162.1 P8.39(20) R64.2 R89.1 U5.T3(LCD_DATA6/GPMC_A6/PR1_EDIO_DATA_IN6/EQEP2_INDEX/PR1_EDIO_DATA_OUT6/PR1_PRU1_PRU_R30_6/PR1_PRU1_PRU_R31_6/GPIO2_12) U11.6(VPB3)
LCD_DATA7: C161.1 P8.40(45) R63.2 R88.1 U5.T4(LCD_DATA7/GPMC_A7/PR1_EDIO_DATA_IN7/EQEP2_STROBE/PR1_EDIO_DATA_OUT7/PR1_PRU1_PRU_R30_7/PR1_PRU1_PRU_R31_7/GPIO2_13) U11.3(VPB4)
LCD_DATA8: C160.1 P8.37(19) R62.2 R87.1 U5.U1(LCD_DATA8/GPMC_A12/EHRPWM1_TRIPZONE_INPUT/MCASP0_ACLKX/UART5_TXD/PR1_MII0_RXD3/UART2_CTSN/GPIO2_14) U11.2(VPB5)
LCD_DATA9: C157.1 P8.38(44) R61.2 R86.1 U5.U2(LCD_DATA9/GPMC_A13/EHRPWM1_SYNCI_O/MCASP0_FSX/UART5_RXD/PR1_MII0_RXD2/UART2_RTSN/GPIO2_15) U11.1(VPB6)
LCD_DATA10: C156.1 P8.36(43) R60.2 R85.1 U5.U3(LCD_DATA10/GPMC_A14/EHRPWM1A/MCASP0_AXR0//PR1_MII0_RXD1/UART3_CTSN/GPIO2_16) U11.64(VPB7)
LCD_DATA11: C168.1 P8.34(42) R59.2 R84.1 U5.U4(LCD_DATA11/GPMC_A15/EHRPWM1B/MCASP0_AHCLKR/MCASP0_AXR2/PR1_MII0_RXD0/UART3_RTSN/GPIO2_17) U11.60(VPA3)
LCD_DATA12: C167.1 P8.35(18) R58.2 R83.1 U5.V2(LCD_DATA12/GPMC_A16/EQEP1A_IN/MCASP0_ACLKR/MCASP0_AXR2/PR1_MII0_RXLINK/UART4_CTSN/GPIO0_8) U11.59(VPA4)
LCD_DATA13: C166.1 P8.33(17) R57.2 R82.1 U5.V3(LCD_DATA13/GPMC_A17/EQEP1B_IN/MCASP0_FSR/MCASP0_AXR3/PR1_MII0_RXER/UART4_RTSN/GPIO0_9) U11.58(VPA5)
LCD_DATA14: C165.1 P8.31(16) R56.2 R81.1 U5.V4(LCD_DATA14/GPMC_A18/EQEP1_INDEX/MCASP0_AXR1/UART5_RXD/PR1_MII_MR0_CLK/UART5_CTSN/GPIO0_10) U11.57(VPA6)
LCD_DATA15: C164.1 P8.32(41) R55.2 R80.1 U5.T5(LCD_DATA15/GPMC_A19/EQEP1_STROBE/MCASP0_AHCLKX/MCASP0_AXR3/PR1_MII0_RXDV/UART5_RTSN/GPIO0_11) U11.56(VPA7)
LCD_DE: P8.30(40) R48.2 U11.20(DE/VREF)
LCD_HSYNC: P8.29(15) R47.2 U11.22(HSYNC/VREF)
LCD_PCLK: P8.28(39) R45.2 U11.4(PCLK)
LCD_VSYNC: P8.27(14) R46.2 U11.21(VSYNC/VREF)
LCDDE: R48.1 U5.R6(LCD_AC_BIAS_EN/GPMC_A11//PR1_EDIO_DATA_IN5/PR1_EDIO_DATA_OUT5/PR1_PRU1_PRU_R30_11/PR1_PRU1_PRU_R31_11/GPIO2_25)
LCDPCLK: R45.1 U5.V5(LCD_PCLK/GPMC_A10//PR1_EDIO_DATA_IN4/PR1_EDIO_DATA_OUT4/PR1_PRU1_PRU_R30_10/PR1_PRU1_PRU_R31_10/GPIO2_24)
LCDVHYNC: R47.1 U5.R5(LCD_HSYNC/GPMC_A9//PR1_EDIO_DATA_IN3/PR1_EDIO_DATA_OUT3/PR1_PRU1_PRU_R30_9/PR1_PRU1_PRU_R31_9/GPIO2_23)
LCDVSYNC: R46.1 U5.U5(LCD_VSYNC/GPMC_A8//PR1_EDIO_DATA_IN2/PR1_EDIO_DATA_OUT2/PR1_PRU1_PRU_R30_8/PR1_PRU1_PRU_R31_8/GPIO2_22)
LDO_PGOOD: U2.46(LDO_PGOOD) U5.B5(RTC_PORZn)
LEDAA: D2.2(A) R72.2
LEDAC: D2.1(C) Q1.6(3)
LEDBA: D3.2(A) R73.2
LEDBC: D3.1(C) Q1.3
LEDCA: D4.2(A) R74.2
LEDCC: D4.1(C) Q2.6(3)
LEDDA: D5.2(A) R71.2
LEDDC: D5.1(C) Q2.3
MDIO_CLK: U5.M18(MDIO_CLK/TIMER5/UART5_TXD/UART3_RTSN/MMC0_SDWP/MMC1_CLK/MMC2_CLK/GPIO0_1) U14.17(MDC)
MDIO_DATA: R119.2 U5.M17(MDIO_DATA/TIMER6/UART5_RXD/UART3_CTSN/MMC0_SDCD/MMC1_CMD/MMC2_CMD/GPIO0_0) U14.16(MDIO)
MII1_COL: R138.1 U5.H16(GMII1_COL/RMII2_REFCLK/SPI1_SCLK/UART5_RXD/MCASP1_AXR2/MMC2_DAT3/MCASP0_AXR2/GPIO3_0)
MII1_CRS_DV: R139.1 U5.H17(GMII1_CRS/RMII1_CRS_DV/SPI1_D0/I2C1_SDA/MCASP1_ACLKX/UART5_CTSN/UART2_RXD/GPIO3_1)
MII1_REFCLK: R28.2 R124.1 R140.1
MII1_RXCLK: R131.1 U5.L18(GMII1_RXCLK/UART2_TXD/RGMII1_RCLK/MMC0_DAT6/MMC1_DAT1/UART1_DSRN/MCASP0_FSX/GPIO3_10)
MII1_RXD0: R128.1 U5.M16(GMII1_RXD0/RMII1_RXD0/RGMII1_RD0/MCASP1_AHCLKX/MCASP1_AHCLKR/MCASP1_ACLKR/MCASP0_AXR3/GPIO2_21)
MII1_RXD1: R127.1 U5.L15(GMII1_RXD1/RMII1_RXD1/RGMII1_RD1/MCASP1_AXR3/MCASP1_FSR/EQEP0_STROBE/MMC2_CLK/GPIO2_20)
MII1_RXD2: R126.1 U5.L16(GMII1_RXD2/UART3_TXD/RGMII1_RD2/MMC0_DAT4/MMC1_DAT3/UART1_RIN/MCASP0_AXR1/GPIO2_19)
MII1_RXD3: R125.1 U5.L17(GMII1_RXD3/UART3_RXD/RGMII1_RD3/MMC0_DAT5/MMC1_DAT2/UART1_DTRN/MCASP0_AXR0/GPIO2_18)
MII1_RXDV: R129.1 U5.J17(GMII1_RXDV/LCD_MEMORY_CLK/RGMII1_RCTL/UART5_TXD/MCASP1_ACLKX/MMC2_DAT0/MCASP0_ACLKR/GPIO3_4)
MII1_RXERR: R133.1 U5.J15(GMII1_RXERR/RMII1_RXERR/SPI1_D1/I2C1_SCL/MCASP1_FSX/UART5_RTSN/UART2_TXD/GPIO3_2)
MII1_TXCLK: R134.1 U5.K18(GMII1_TXCLK/UART2_RXD/RGMII1_TCLK/MMC0_DAT7/MMC1_DAT0/UART1_DCDN/MCASP0_ACLKX/GPIO3_9)
MII1_TXD0: U5.K17(GMII1_TXD0/RMII1_TXD0/RGMII1_TD0/MCASP1_AXR2/MCASP1_ACLKR/EQEP0B_IN/MMC1_CLK/GPIO0_28) U14.22(TXD0)
MII1_TXD1: U5.K16(GMII1_TXD1/RMII1_TXD1/RGMII1_TD1/MCASP1_FSR/MCASP1_AXR1/EQEP0A_IN/MMC1_CMD/GPIO0_21) U14.23(TXD1)
MII1_TXD2: U5.K15(GMII1_TXD2/DCAN0_RX/RGMII1_TD2/UART4_TXD/MCASP1_AXR0/MMC2_DAT2/MCASP0_AHCLKX/GPIO0_17) U14.24(TXD2)
MII1_TXD3: U5.J18(GMII1_TXD3/DCAN0_TX/RGMII1_TD3/UART4_RXD/MCASP1_FSX/MMC2_DAT1/MCASP0_FSR/GPIO0_16) U14.25(TXD3)
MII1_TXEN: U5.J16(GMII1_TXEN/RMII1_TXEN/RGMII1_TCTL/TIMER4/MCASP1_AXR0/EQEP0_INDEX/MMC2_CMD/GPIO3_3) U14.21(TXEN)
MMC0_CD: P2.19(EMU4) P10.10(CD) R157.1 U5.C15(SPI0_CS1/UART3_RXD/ECAP1_IN_PWM1_OUT/MMC0_POW/XDMA_EVENT_INTR2/MMC0_SDCD/EMU4/GPIO0_6)
MMC0_CLKO: P10.5(CLOCK) R152.2 U5.G17(MMC0_CLK/GPMC_A24/UART3_CTSN/UART2_RXD/DCAN1_TX/PR1_PRU0_PRU_R30_12/PR1_PRU0_PRU_R31_12/GPIO2_30)
MMC0_CMD: P10.3(CMD) R151.2 U5.G18(MMC0_CMD/GPMC_A25/UART3_RTSN/UART2_TXD/DCAN1_RX/PR1_PRU0_PRU_R30_13/PR1_PRU0_PRU_R31_13/GPIO2_31)
MMC0_DAT0: P10.7(DAT0) R153.2 U5.G16(MMC0_DAT0/GPMC_A23/UART5_RTSN/UART3_TXD/UART1_RIN/PR1_PRU0_PRU_R30_11/PR1_PRU0_PRU_R31_11/GPIO2_29)
MMC0_DAT1: P10.8(DAT1) R154.2 U5.G15(MMC0_DAT1/GPMC_A22/UART5_CTSN/UART3_RXD/UART1_DTRN/PR1_PRU0_PRU_R30_10/PR1_PRU0_PRU_R31_10/GPIO2_28)
MMC0_DAT2: P10.1(DAT2) R150.2 U5.F18(MMC0_DAT2/GPMC_A21/UART4_RTSN/TIMER6/UART1_DSRN/PR1_PRU0_PRU_R30_9/PR1_PRU0_PRU_R31_9/GPIO2_27)
MMC0_DAT3: P10.2(CD/DAT3) R155.2 U5.F17(MMC0_DAT3/GPMC_A20/UART4_CTSN/TIMER5/UART1_DCDN/PR1_PRU0_PRU_R30_8/PR1_PRU0_PRU_R31_8/GPIO2_26)
MMC1_CLK: P8.21(11) R110.2 U5.U9(GPMC_CSN1/GPMC_CLK/MMC1_CLK/PRT1EDIO_DATA_IN6/PRT1_EDIO_DATA_OUT6/PR1_PRU1_PRU_R30_12/PR1_PRU1_PRU_R31_12/GPIO1_30) U13.M6(CLK)
MMC1_CMD: P8.20(35) R109.2 U5.V9(GPMC_CSN2/GPMC_BE1N/MMC1_CMD/PR1_EDIO_DATA_IN7/PR1_EDIO_DATA_OUT7/PR1_PRU1_PRU_R30_13/PR1_PRU1_PRU_R31_13/GPIO1_31) U13.M5(CMD)
MMC1_DAT0: P8.25(13) R101.2 U5.U7(GPMC_AD0/MMC1_DAT0//////GPIO1_0) U13.A3(DAT0)
MMC1_DAT1: P8.24(37) R102.2 U5.V7(GPMC_AD1/MMC1_DAT1//////GPIO1_1) U13.A4(DAT1)
MMC1_DAT2: P8.5(3) R103.2 U5.R8(GPMC_AD2/MMC1_DAT2//////GPIO1_2) U13.A5(DAT2)
MMC1_DAT3: P8.6(28) R104.2 U5.T8(GPMC_AD3/MMC1_DAT3//////GPIO1_3) U13.B2(DAT3)
MMC1_DAT4: P8.23(12) R105.2 U5.U8(GPMC_AD4/MMC1_DAT4//////GPIO1_4) U13.B3(DAT4)
MMC1_DAT5: P8.22(36) R106.2 U5.V8(GPMC_AD5/MMC1_DAT5//////GPIO1_5) U13.B4(DAT5)
MMC1_DAT6: P8.3(2) R107.2 U5.R9(GPMC_AD6/MMC1_DAT6//////GPIO1_6) U13.B5(DAT6)
MMC1_DAT7: P8.4(27) R108.2 U5.T9(GPMC_AD7/MMC1_DAT7//////GPIO1_7) U13.B6(DAT7)
MODE2: R113.1 R138.2 U14.15(COL/CRS_DV/MODE2)
OSC0_IN: C25.1 R17.1 U5.V10(OSC0_IN) Y2.2
OSC0_OUT: C26.1 R17.2 U5.U11(OSC0_OUT) Y2.1
OSC1_IN: C21.2 U5.A6(OSC1_IN) Y1.1
OSC1_OUT: C22.2 U5.A4(OSC1_OUT) Y1.4
P_BYPASS: C4.2 U2.47(BYPASS)
P_INT_LDO: C3.2 U2.48(INT_LDO)
P_L1: L1.1 U2.20(L1)
P_L2: L2.1 U2.23(L2)
P_L3: L3.1 U2.31(L3)
PHY_VDDCR: C134.1 C136.1 U14.6(VDDCR)
PHY_XTAL1: C143.1 R141.2 R142.1 Y3.1
PHY_XTAL2: R141.1 R143.1 U14.4(XTAL2)
PHYX: C142.1 R143.2 Y3.2
PMIC_INT: R1.2 U2.45(INT) U5.B18(NNMI)
PMIC_PGOOD: U2.26(PGOOD) U5.B15(PORZn) U16.2(A)
PMIC_POWR_EN: U2.9(PWR_EN) U5.C6(PMIC_POWER_EN)
PROC_A15: R18.1 U5.A15(EVENT_INTR0/TIMER4/CLKOUT1/SPI1_CS1/PR1PRU1R31_16/EMU2/GPIO0_19)
PWR_BUT: P9.9(5) S3.2(B1) S3.4(B2) U2.25(PB_IN)
PWR_LEDR: D1.1(C) R12.2
RBIAS: R144.1 U14.32(RBIAS)
RCLKIN: R140.2 R142.2 U14.5(XTAL1/CLKIN)
REFCLKO: R118.1 R124.2 R131.2 U14.7(RXCLK/PHYAD1)
RXD0/MODE0: R112.1 R128.2 U14.11(RXD0/MODE0)
RXD1/MODE1: R114.1 R127.2 U14.10(RXD1/MODE1)
RXD2/RMIISEL: R117.1 R126.2 U14.9(RXD2/RMIISEL)
RXD3/PHYAD2: R116.1 R125.2 U14.8(RXD3/PHYAD2)
RXDV: R129.2 U14.26(RXDV)
RXER/PHYAD0: R115.1 R133.2 U14.13(RXER/RXD4/PHYAD0)
RXN: C138.1 P5.2(RD-) R121.1 U14.30(RXN)
RXP: C137.1 P5.1(RD+) R120.1 U14.31(RXP)
SPI1_CS0: P9.28(39) U5.C12(MCASP0_AHCLKR/EHRPWM0_SYNCI_O/MCASP0_AXR2/SPI1_CS0/ECAP2_IN_PWM2_OUT/PR1_PRU0_PRU_R30_3/PR1_PRU0_PRU_R31_3/GPIO3_17) U11.25(AP1)
SPI1_D0: P9.29(15) U5.B13(MCASP0_FSX/EHRPWM0B//SPI1_D0/MMC1_SDCD/PR1_PRU0_PRU_R30_1/PR1_PRU0_PRU_R31_1/GPIO3_15) U11.24(AP0)
SPI1_D1: P9.30(40) U5.D12(MCASP0_AXR0/EHRPWM0_TRIPZONE_INPUT//SPI1_D1/MMC2_SDCD/PR1_PRU0_PRU_R30_2/PR1_PRU0_PRU_R31_2/GPIO3_16)
SPI1_SCLK: P9.31(16) U5.A13(MCASP0_ACLKX/EHRPWM0A//SPI1_SCLK/MMC0_SDCD/PR1_PRU0_PRU_R30_0/PR1_PRU0_PRU_R31_0/GPIO3_14) U11.23(ACLK)
SYS_5V: C7.2 C8.2 C10.2 C13.2 C17.1 C34.1 P9.7(4) P9.8(29) R71.1 R72.1 R73.1 R74.1 RT1.1 U2.2(VINLDO) U2.7(SYS1) U2.8(SYS2) U2.21(VIN_DCDC1) U2.22(VIN_DCDC2) U2.32(VIN_DCDC3) U2.39(LDO3_IN) U2.42(LDO4_IN) U4.2(IN) U8.2(IN1) U8.3(IN2)
SYS_RESETn: C24.1 C30.1 P2.15(SRST) P9.10(30) R14.2 S1.2(B1) S1.4(B2) U5.A10(NRESET_INOUT) U14.19(nRST) U16.4(Y)
TCT_RCT: C141.1 P5.4(RCT) P5.5(TCT) R137.1
TESTOUT: TP3.1(TP) U5.A3(TESTOUT)
TIMER4: P8.7(4) U5.R7(GPMC_ADVN_ALE/TIMER4/GPIO2_2)
TIMER5: P8.9(5) U5.T6(GPMC_BE0N_CLE/TIMER5/GPIO2_5)
TIMER6: P8.10(30) U5.U6(GPMC_WEN/TIMER6/GPIO2_4)
TIMER7: P8.8(29) U5.T7(GPMC_OEN_REN/TIMER7/EMU4/GPIO2_3)
TXCLK: R134.2 U14.20(TXCLK)
TXN: C140.1 P5.6(TD-) R123.1 U14.28(TXN)
TXP: C139.1 P5.3(TD+) R122.1 U14.29(TXP)
U5_H18: R28.1 U5.H18(RMII1_REFCLK/XDMA_EVENT_INTR2/SPI1_CS0/UART5_TXD/MCASP1_AXR3/MMC0_POW/MCASP1_AHCLKX/GPIO0_29)
U5_R13: R160.1 U5.R13(GPMC_A0/GMII2_TXEN/RGMII2_TCTL/RMII2_TXEN/GPMC_A16/PR1_MII_MT1_CLK/EHRPWM1_TRIPZONE_INPUT/GPIO1_16)
U5_T13: R161.1 U5.T13(GPMC_CSN3/MMC2_CMD/PR1_MDIO_DATA/GPIO2_0)
UART0_RX: U5.E15(UART0_RXD/SPI1_CS0/DCAN0_TX/I2C2_SDA/ECAP2_IN_PWM2_OUT/PR1_PRU1_PRU_R30_14/PR1_PRU1_PRU_R31_14/GPIO1_10) U15.6(1Y)
UART0_TX: U5.E16(UART0_TXD/SPI1_CS1/DCAN0_RX/I2C2_SCL/ECAP1_IN_PWM1_OUT/PR1_PRU1_PRU_R30_15/PR1_PRU1_PRU_R31_15/GPIO1_11) U15.5(2A)
UART1_RXD: P9.26(38) U5.D16(UART1_RXD/MMC1_SDWP/DCAN1_TX/I2C1_SDA//PR1_UART0_RXD/PR1_PRU1_PRU_R31_16/GPIO0_14)
UART1_TXD: P9.24(37) U5.D15(UART1_TXD/MMC2_SDWP/DCAN1_RX/I2C1_SCL//PR1_UART0_TXD/PR1_PRU0_PRU_R31_16/GPIO0_15)
UART2_RXD: P9.22(36) U5.A17(SPI0_SCLK/UART2_RXD/I2C2_SDA/EHRPWM0A/PR1_UART0_CTS_N/PR1_EDIO_SOF/EMU2/GPIO0_2)
UART2_TXD: P9.21(11) U5.B17(SPI0_D0/UART2_TXD/I2C2_SCL/EHRPWM0B/PR1_UART0_RTS_N/PR1_EDIO_LATCH_IN/EMU3/GPIO0_3)
UART4_RXD: P9.11(6) U5.T17(GPMC_WAIT0/GM112_CRS/GPMC_CSN4/RMII2_CRS_DV/MMC1_SDCD/PR1_MII1_RXDV/UART4_RXD/GPIO0_30)
UART4_TXD: P9.13(7) U5.U17(GPMC_WPN/GMII2_RXERR/GPMC_CSN5/RMII2_RXERR/MMC2_SDCD/PR1_MDIO_MDCLK/UART4_TXD/GPIO0_31)
USB0_DM: P4.2(D-) U5.N18(USB0_DM) U10.2(D-)
USB0_DP: P4.3(D+) U5.N17(USB0_DP) U10.1(D+)
USB0_ID: P4.4(ID) U5.P16(USB0_ID) U10.3(ID)
USB1_DM: P3.2(P2) U5.R18(USB1_DM) U9.2(D-)
USB1_DP: P3.3(P3) U5.R17(USB1_DP) U9.1(D+)
USB1_DRVVBUS: R53.1 U5.F15(USB1_DRVVBUS/GPIO3_13) U8.4(EN)
USB1_ID: R49.2 U5.P17(USB1_ID)
USB1_OCn: R52.2 U5.T16(GPMC_A10/GMII2_RXD1/RGMII2_RD1/RMII2_RXD1/GPMC_A26/PR1_MII1_CRS/MCASP0_AXR0/GPIO1_26) U8.5(~{OC})
USB1_PWR: C35.1 FB7.1 FB8.2 U8.6(OUT3) U8.7(OUT2) U8.8(OUT1) U9.6(VBUS)
USB1_VBUS: FB8.1 U5.T18(USB1_VBUS)
USB_DC: C1.2 C36.1 P4.1(VB) R159.1 U2.12(USB) U10.6(VBUS)
USR0: Q1.2(5) R76.1 U5.V15(GPMC_A5/GMII2_TXD0/RGMII2_TD0/RMII2_TXD0/GPMC_A21/PR1_MII1_RXD3/EQEP1B_IN/GPIO1_21)
USR1: Q1.5 R77.1 U5.U15(GPMC_A6/GMII2_TXCLK/RGMII2_TCLK/MMC2_DAT4/GPMC_A22/PR1_MII1_RXD2/EQEP1_INDEX/GPIO1_22)
USR2: Q2.2(5) R78.1 U5.T15(GPMC_A7/GMII2_RXCLK/RGMII2_RCLK/MMC2_DAT5/GPMC_A23/PR1_MII1_RXD1/EQEP1_STROBE/GPIO1_23)
USR3: Q2.5 R79.1 U5.V16(GPMC_A8/GMII2_RXD3/RGMII2_RD3/MMC2_DAT6/GPMC_A24/PR1_MII1_RXD0/MCASP0_ACLKX/GPIO1_24)
VDCDC1: L1.2 R6.1 U2.19(VDCDC1)
VIO: R7.2 U2.18(VIO) U16.5(VCC)
VLDO1: R5.1 R7.1 R8.1 U2.3(VLDO1)
VREFP_ADC: C31.1 C32.1 C33.1 R27.2 U5.B9(VREFP)
VRTC: C16.1 C105.1 R5.2 R26.1 U5.D7(VDDS_RTC)
WAKEUP: R26.2 U2.13(WAKEUP) U5.C5(EXT_WAKEUP)
WP: R156.2 TP4.1(TP) U7.5(WP)
XDMA_EVENT_INTR0: P2.17(EMU2) R18.2 U6.1(CLK)
YEL_C: P5.11(YELC) R130.2
YELA: P5.12(YELA) R135.1 U14.2(LED2/nINTSEL)
ZQ: R99.2 U12.L8(ZQ)
N21667305: R149.1 U11.49(TEST)
N21757673: C19.1 R10.1 R11.2 U4.4(ADJ)
N21769115: R75.2 S2.1(A1) S2.3(A2)
N22155575: R159.2 U5.P15(USB0_VBUS)
N22248684: R167.1 Y4.3(CLK)
N22248838: R21.1 U6.5(Q)
N22287501: R162.1 U3.4(Y)
N22287555: U3.2(A) U5.R14(GPMC_A4/GMII2_TXD1/RGMII2_TD1/RMII2_TXD1/GPMC_A20/PR1_MII1_TXD0/EQEP1A_IN/GPIO1_20)
N22420400: TP5.1(TP) U2.4(BAT1) U2.5(BAT2)
N22420444: TP6.1(TP) U2.6(BAT_SENSE)
N22420447: TP7.1(TP) U2.11(TS)
N22488252: TP9.1(TP) U5.E17(UART0_RTSN/UART4_TXD/DCAN1_RX/I2C1_SCL/SPI1_D1/SPI1_CS0/PR1_EDC_SYNC1_OUT/GPIO1_9)

Not connected (* = marked no-connect by the designer): D6 6* 7* 9* 10*; D7 6* 7* 9* 10*; J1 2* 3* 6*; P1 3; P2 6(NC)*; P5 7(NC)*; P6 2(NC)*; U2 14(MUX_IN)* 15(NC)* 16(MUX_OUT)* 17(NC1)* 33(ISINK2)* 34(ISINK1)* 35(ISET1)* 36(ISET2)* 37(L4)* 38(FB_WLED)* 44(RESET)*; U3 1(NC)*; U5 E18(UART0_CTSN/UART4_RXD/DCAN1_TX/I2C1_SDA/SPI1_D0/TIMER7/PR1_EDC_SYNC0_OUT/GPIO1_8)* F16(USB0_DRVVBUS/GPIO0_18) M5(VPP) M15(USB0_CE) P18(USB1_CE); U9 3(ID)* 5(NC)*; U10 5(NC)*; U11 26(AP2)* 28(AP3)*; U12 J1(NC1)* J9(NC2)* L1(NC3)* L9(NC4)*; U13 A1(NC11)* A2(NC4)* A6(NC5)* A7(NC6)* A8(NC7)* A9(NC18)* A10(NC95)* A11(NC94)* A12(NC93)* A13(NC92)* A14(NC91)* B1(NC90)* B7(NC89)* B8(NC74)* B9(NC53)* B10(NC52)* B11(NC51)* B12(NC50)* B13(NC49)* B14(NC19)* C1(NC34)* C3(NC33)* C5(NC32)* C7(NC31)* C8(NC30)* C9(NC29)* C10(NC25)* C11(NC23)* C12(NC22)* C13(NC21)* C14(NC20)* D1(NC48)* D2(NC46)* D3(NC39)* D4(NC38)* D12(NC37)* D13(NC36)* D14(NC35)* E1(NC1)* E2(NC2)* E3(NC3)* E5(NC121)* E8(NC8)* E9(NC9)* E10(NC10)* E12(NC12)* E13(NC13)* E14(NC14)* F1(NC15)* F2(NC16)* F3(NC17)* F10(NC24)* F12(NC26)* F13(NC27)* F14(NC28)* G1(NC88)* G2(NC81)* G3(NC79)* G10(NC78)* G12(NC40)* G13(NC41)* G14(NC42)* H1(NC43)* H2(NC44)* H3(NC45)* H5(NC47)* H12(NC54)* H13(NC55)* H14(NC56)* J1(NC57)* J2(NC58)* J3(NC59)* J5(NC60)* J12(NC117)* J13(NC69)* J14(NC70)* K1(NC71)* K2(NC72)* K3(NC73)* K6(NC123)* K7(NC77)* K10(NC80)* K12(NC82)* K13(NC83)* K14(NC84)* L1(NC85)* L2(NC86)* L3(NC87)* L12(NC96)* L13(NC97)* L14(NC98)* M1(NC99)* M2(NC100)* M3(NC101)* M7(NC105)* M8(NC106)* M9(NC107)* M10(NC108)* M11(NC109)* M12(NC110)* M13(NC111)* M14(NC112)* N1(NC113)* N3(NC115)* N6(NC122)* N7(NC118)* N8(NC119)* N9(NC120)* N10(NC75)* N11(NC76)* N12(NC68)* N13(NC67)* N14(NC66)* P1(NC65)* P2(NC64)* P7(NC63)* P8(NC61)* P9(NC62)* P10(NC114)* P11(NC104)* P12(NC103)* P13(NC102)* P14(NC116)*; U16 1(NC)*; Y1 2* 3*

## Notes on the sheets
sheet 1
- REV
- Description
- DATE
- BY
- A4A
- Initial production Release.
- 11/19/2012
- GC
- A5
- On the initial production release the processors were to be found incorrect as supplied by TI.
  Parts while marked AM3359 were actually AM3352. This revision uses the correct parts.
- 1/2/2013
- GC
- PAGE NO.
- SCHEMATIC PAGE
- 1. Deleted R29-R44 from the LCD lines.
- 1
- COVER PAGE
- 2. Added 47pf capacitors C156-C173 to LCD data lines to ground.
- 3. Changed schematic revision to A5A.
- 2
- POWER MANAGEMENT
- 4. Changed a few footprints after PCB update for above changes.
- 3
- PROCESSOR 1 OF 3, JTAG HEADER
- 5. Added access point for the battery function of the TPS65217C.
- A5A
- 2/8/2013
- GC
- 4
- PROCESSOR 2 OF 3, UAB PORTS
- 6. Added Ferrite beads in series with LED power and 5V power rail of the USB host
  connector. Required to pass FCC/CE testing due to noise emissions on that pin.
- 7. Added power button to enable sleep, wakeup, power down and power up  features on the
  system.
- 5
- PROCESSOR 3 OF 3
- 6
- LED, CONFIGURATION AND BUTTON
- 8. Added Modification to add 100K ohm resistor to ground to prvent crosstalk when serial
  cable is not plugged in.
- 7
- DDR3 MEMORY
- 1. Added 100K pulldown on J1 pin 4 to prevent crosstalk when serial cable is
  not connected into PCB layout.
  2. Changed the LED resistors to 4.75K to lower the brightness.
- A5B
- 5/21/2013
- GC
- 8
- eMMC FLASH
- 1. Changed R46, R47,R48 to 0 ohms.
  2. Changed R45 to 22 Ohms.
  Change was made due to production failures on some boards due to differences in impedances.
- 9
- 10/100 ETHERNET
- A5C
- 6/12/2013
- GC
- 10
- HDMI FRAMER
- 1. Moved the enable for the VDD_3V3B regulator to VDD_3V3A rail. Change was made to
  reduce the delay between the ramp up of the 3.3V rails.
- 11
- EXP CONN, uSD
- 2. Added a AND gate to the SYS_RESETn circuitry. There is a small chance that on power up
  the nRESETOUT signal on the processor may go high, causing the SYS_RESETn signal to go
  HI before it should. This change reenforces the reset with the PORZn reset  signal.
- A6
- 7/25/2013
- GC
- 3. Added optional zero ohm resistor to tie GND_OSC0 to system ground.
- 1. Added optional zero ohm resistor to tie GND_OSC1 to system ground.
- 2. Changed C106 to a 1uF capacitor.
- 12/13/2013
- GC
- A6A
- 3. Changed C24 to a  2.2uF capacitor.
- NOTE: PCB Revision for this board is Rev B6
- 4. Made R8 installed and R9 not installed.
- B
- 1.Changed the processor to the AM3358BZCZ100.
- 1/20/2014
- GC
- This schematic is  *NOT SUPPORTED* and DOES NOT constitute
  a reference design. Only “community” support is allowed
  via resources at BeagleBoard.org/discuss.
  THERE IS NO WARRANTY FOR THIS DESIGN , TO THE EXTENT
  PERMITTED BY APPLICABLE LAW. EXCEPT WHEN OTHERWISE STATED
  IN WRITING THE COPYRIGHT HOLDERS AND/OR OTHER PARTIES
  PROVIDE THE DESIGN “AS IS” WITHOUT WARRANTY OF ANY KIND,
  EITHER EXPRESSED OR IMPLIED, INCLUDING, BUT NOT LIMITED
  TO, THE IMPLIED WARRANTIES OF MERCHANTABILITY AND FITNESS
  FOR A PARTICULAR PURPOSE. THE ENTIRE RISK AS TO THE
  QUALITY AND PERFORMANCE OF THE DESIGN IS WITH YOU. SHOULD
  THE DESIGN PROVE DEFECTIVE, YOU ASSUME THE COST OF ALL
  NECESSARY SERVICING, REPAIR OR CORRECTION.
sheet 2
- Battery access pins. Pins
  are randomly placed to fit
  them in, but will be able to
  tie into them either with a
  cape or wires. Pins will not
  be populated.
- POWER BUTTON
- 1.5V
- POWER LED
- 500mA
sheet 3
- SYS_BOOT0
- SYS_BOOT1
- uSD BOOT
- USR0
- USR1
- USR2
- USR3
- SYS_BOOT2
- SYS_BOOT3
- SYS_BOOT4
- SYS_BOOT5
- User LED's
- SYS_BOOT6
- SYS_BOOT7
- SYS_BOOT8
- SYS_BOOT9
- SYS_BOOT10
- SYS_BOOT11
- SYS_BOOT12
- SYS_BOOT13
- SYS_BOOT14
- SYS_BOOT15
- Boot Configuration
sheet 4
- DDR3L SDRAM
- 4Gb DDR3
sheet 6
- RED
- GREEN
- BLUE
- McASP0_ACLKX (Pin A13 Mode 0)
- McASP0_AXR2 (Pin C12 Mode 2)
- McASP0_FSX  (Pin B13 Mode 0)
sheet 7
- CAUTION: USED ON BOARD
- CAUTION: USED ON BOARD
- EXPANSION HEADER
- EXPANSION HEADER
- Board ID
- 256KX8
- uSD CONNECTOR
sheet 9
- 3.3V
- RESET
- 1.8V
- 1.8V
- 3.3V
- H
- CEC Clock for HDMI Framer
- External clock to the
  McASP0 interface.
- Oscillator can be disabled via SW
  for power down modes or if
  GPIO3_21 needs to be used.
sheet 10
- ETHERNET
  CONNECTOR
- ESD_RING
- ACTIVE WHEN LINK PRESENT.
  BLINKS OFF DURING ACTIVITY.
- ACTIVE WHEN AT 100MB
sheet 11
- Mark pin 1 clearly
- POWERDOWN ISOLATION
- UART0 Serial Port
- USB to TTL
  Serial Cable
  3.3V
- USB PC
  CONNECTOR
- USB HOST
